Omron CX-Programmer project 新工程 (CX-Programmer 9.50)

# PLC 新PLC1: CP1E N14

## Global symbols (name address type ; comment)
0.00 BOOL  ; 编码器输入
0.04 BOOL  ; 工位1剔除输入
0.05 BOOL  ; 工位2剔除输入
0.06 BOOL  ; 工位3剔除输入
0.07 BOOL  ; 喷码剔除输入
100.00 BOOL  ; 剔除输出
100.01 BOOL  ; 剔除
D0 CHANNEL  ; 1#计数器当前值
D10 CHANNEL  ; 一
D12 CHANNEL  ; 一
D14 CHANNEL  ; 一
D16 CHANNEL  ; 一
D18 CHANNEL  ; 一
D2 CHANNEL  ; 一
D20 CHANNEL  ; 一
D200 CHANNEL  ; 2#计数器当前值
D2000 CHANNEL  ; 相机1脉冲数
D2002 CHANNEL  ; 相机2脉冲数
D2004 CHANNEL  ; 相机3脉冲数
D2006 CHANNEL  ; 相机4脉冲数
D2008 CHANNEL  ; 吹气时间
D202 CHANNEL  ; 二
D204 CHANNEL  ; 二
D206 CHANNEL  ; 二
D208 CHANNEL  ; 二
D210 CHANNEL  ; 二
D212 CHANNEL  ; 二
D214 CHANNEL  ; 二
D216 CHANNEL  ; 二
D218 CHANNEL  ; 二
D22 CHANNEL  ; 一
D220 CHANNEL  ; 二
D222 CHANNEL  ; 二
D224 CHANNEL  ; 二
D226 CHANNEL  ; 二
D228 CHANNEL  ; 二
D230 CHANNEL  ; 二
D232 CHANNEL  ; 二
D234 CHANNEL  ; 二
D236 CHANNEL  ; 二
D238 CHANNEL  ; 二
D24 CHANNEL  ; 一
D240 CHANNEL  ; 二
D242 CHANNEL  ; 二
D244 CHANNEL  ; 二
D246 CHANNEL  ; 二
D248 CHANNEL  ; 二
D250 CHANNEL  ; 二
D252 CHANNEL  ; 二
D254 CHANNEL  ; 二
D256 CHANNEL  ; 二
D258 CHANNEL  ; 二
D26 CHANNEL  ; 一
D260 CHANNEL  ; 二
D28 CHANNEL  ; 一
D30 CHANNEL  ; 一
D32 CHANNEL  ; 一
D34 CHANNEL  ; 一
D36 CHANNEL  ; 一
D38 CHANNEL  ; 一
D4 CHANNEL  ; 一
D40 CHANNEL  ; 一
D402 CHANNEL  ; 三
D404 CHANNEL  ; 三
D406 CHANNEL  ; 三
D408 CHANNEL  ; 三
D410 CHANNEL  ; 三
D412 CHANNEL  ; 三
D414 CHANNEL  ; 三
D416 CHANNEL  ; 三
D418 CHANNEL  ; 三
D42 CHANNEL  ; 一
D420 CHANNEL  ; 三
D422 CHANNEL  ; 三
D424 CHANNEL  ; 三
D426 CHANNEL  ; 三
D428 CHANNEL  ; 三
D430 CHANNEL  ; 三
D432 CHANNEL  ; 三
D434 CHANNEL  ; 三
D436 CHANNEL  ; 三
D438 CHANNEL  ; 三
D44 CHANNEL  ; 一
D440 CHANNEL  ; 三
D442 CHANNEL  ; 三
D444 CHANNEL  ; 三
D446 CHANNEL  ; 三
D448 CHANNEL  ; 三
D450 CHANNEL  ; 三
D452 CHANNEL  ; 三
D454 CHANNEL  ; 三
D456 CHANNEL  ; 三
D458 CHANNEL  ; 三
D46 CHANNEL  ; 一
D460 CHANNEL  ; 三
D48 CHANNEL  ; 一
D50 CHANNEL  ; 一
D52 CHANNEL  ; 一
D54 CHANNEL  ; 一
D56 CHANNEL  ; 一
D58 CHANNEL  ; 一
D6 CHANNEL  ; 一
D60 CHANNEL  ; 一
D6000 CHANNEL  ; 喷码延时时间
D602 CHANNEL  ; 四
D604 CHANNEL  ; 四
D606 CHANNEL  ; 四
D608 CHANNEL  ; 四
D610 CHANNEL  ; 四
D612 CHANNEL  ; 四
D614 CHANNEL  ; 四
D616 CHANNEL  ; 四
D618 CHANNEL  ; 四
D620 CHANNEL  ; 四
D622 CHANNEL  ; 四
D624 CHANNEL  ; 四
D626 CHANNEL  ; 四
D628 CHANNEL  ; 四
D630 CHANNEL  ; 四
D632 CHANNEL  ; 四
D634 CHANNEL  ; 四
D636 CHANNEL  ; 四
D638 CHANNEL  ; 四
D640 CHANNEL  ; 四
D642 CHANNEL  ; 四
D644 CHANNEL  ; 四
D646 CHANNEL  ; 四
D648 CHANNEL  ; 四
D650 CHANNEL  ; 四
D652 CHANNEL  ; 四
D654 CHANNEL  ; 四
D656 CHANNEL  ; 四
D658 CHANNEL  ; 四
D660 CHANNEL  ; 四
D8 CHANNEL  ; 一
W0.00 BOOL  ; 一
W0.01 BOOL  ; 一
W0.02 BOOL  ; 一
W0.03 BOOL  ; 一
W0.04 BOOL  ; 一
W0.05 BOOL  ; 一
W0.06 BOOL  ; 一
W0.07 BOOL  ; 一
W0.08 BOOL  ; 一
W0.09 BOOL  ; 一
W0.10 BOOL  ; 一
W0.11 BOOL  ; 一
W0.12 BOOL  ; 一
W0.13 BOOL  ; 一
W0.14 BOOL  ; 一
W0.15 BOOL  ; 一
W10.00 BOOL  ; 二
W10.01 BOOL  ; 二
W10.02 BOOL  ; 二
W10.03 BOOL  ; 二
W10.04 BOOL  ; 二
W10.05 BOOL  ; 二
W10.06 BOOL  ; 二
W10.07 BOOL  ; 二
W10.08 BOOL  ; 二
W10.09 BOOL  ; 二
W10.10 BOOL  ; 二
W10.11 BOOL  ; 二
W10.12 BOOL  ; 二
W10.13 BOOL  ; 二
W10.14 BOOL  ; 二
W10.15 BOOL  ; 二
W11.00 BOOL  ; 二
W11.01 BOOL  ; 二
W11.02 BOOL  ; 二
W11.03 BOOL  ; 二
W11.04 BOOL  ; 二
W11.05 BOOL  ; 二
W11.06 BOOL  ; 二
W11.07 BOOL  ; 二
W11.08 BOOL  ; 二
W11.09 BOOL  ; 二
W11.10 BOOL  ; 二
W11.11 BOOL  ; 二
W11.12 BOOL  ; 二
W11.13 BOOL  ; 二
W11.14 BOOL  ; 二
W11.15 BOOL  ; 二
W1.00 BOOL  ; 一
W1.01 BOOL  ; 一
W1.02 BOOL  ; 一
W1.03 BOOL  ; 一
W1.04 BOOL  ; 一
W1.05 BOOL  ; 一
W1.06 BOOL  ; 一
W1.07 BOOL  ; 一
W1.08 BOOL  ; 一
W1.09 BOOL  ; 一
W1.10 BOOL  ; 一
W1.11 BOOL  ; 一
W1.12 BOOL  ; 一
W1.13 BOOL  ; 一
W1.14 BOOL  ; 一
W1.15 BOOL  ; 一
W20.00 BOOL  ; 三
W20.01 BOOL  ; 三
W20.02 BOOL  ; 三
W20.03 BOOL  ; 三
W20.04 BOOL  ; 三
W20.05 BOOL  ; 三
W20.06 BOOL  ; 三
W20.07 BOOL  ; 三
W20.08 BOOL  ; 三
W20.09 BOOL  ; 三
W20.10 BOOL  ; 三
W20.11 BOOL  ; 三
W20.12 BOOL  ; 三
W20.13 BOOL  ; 三
W20.14 BOOL  ; 三
W20.15 BOOL  ; 三
W21.00 BOOL  ; 三
W21.01 BOOL  ; 三
W21.02 BOOL  ; 三
W21.03 BOOL  ; 三
W21.04 BOOL  ; 三
W21.05 BOOL  ; 三
W21.06 BOOL  ; 三
W21.07 BOOL  ; 三
W21.08 BOOL  ; 三
W21.09 BOOL  ; 三
W21.10 BOOL  ; 三
W21.11 BOOL  ; 三
W21.12 BOOL  ; 三
W21.13 BOOL  ; 三
W21.14 BOOL  ; 三
W21.15 BOOL  ; 三
W30.00 BOOL  ; 四五
W30.01 BOOL  ; 四五
W30.02 BOOL  ; 四五
W30.03 BOOL  ; 四五
W30.04 BOOL  ; 四五
W30.05 BOOL  ; 四五
W30.06 BOOL  ; 四五
W30.07 BOOL  ; 四五
W30.08 BOOL  ; 四五
W30.09 BOOL  ; 四五
W30.10 BOOL  ; 四五
W30.11 BOOL  ; 四五
W30.12 BOOL  ; 四五
W30.13 BOOL  ; 四五
W30.14 BOOL  ; 四五
W30.15 BOOL  ; 四五
W31.00 BOOL  ; 四五
W31.01 BOOL  ; 四五
W31.02 BOOL  ; 四五
W31.03 BOOL  ; 四五
W31.04 BOOL  ; 四五
W31.05 BOOL  ; 四五
W31.06 BOOL  ; 四五
W31.07 BOOL  ; 四五
W31.08 BOOL  ; 四五
W31.09 BOOL  ; 四五
W31.10 BOOL  ; 四五
W31.11 BOOL  ; 四五
W31.12 BOOL  ; 四五
W31.13 BOOL  ; 四五
W31.14 BOOL  ; 四五
W31.15 BOOL  ; 四五

## Program 新程序1 (cyclic task 0)

### Section 脉冲设置

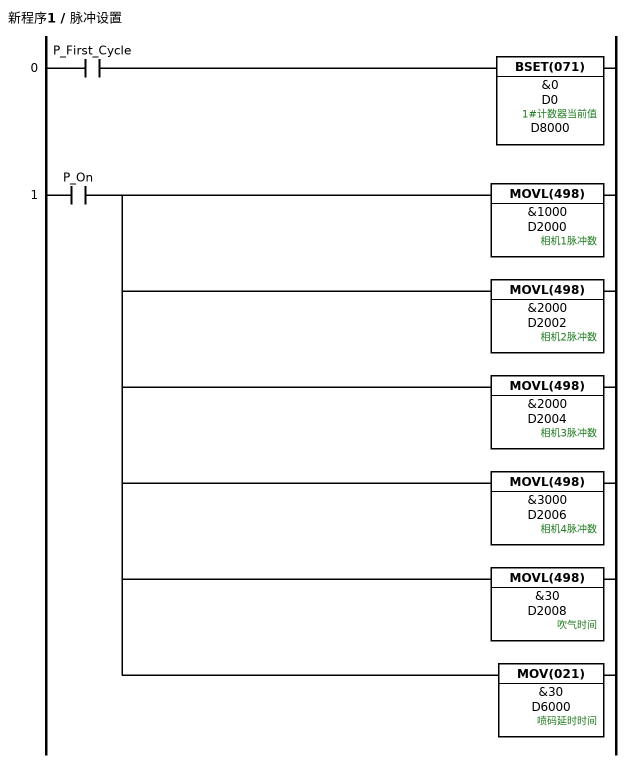
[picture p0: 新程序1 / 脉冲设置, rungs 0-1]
; rung 0
LD P_First_Cycle
BSET(071) &0 D0 D8000  ; 1#计数器当前值
; rung 1
LD P_On
MOVL(498) &1000 D2000  ; 相机1脉冲数
MOVL(498) &2000 D2002  ; 相机2脉冲数
MOVL(498) &2000 D2004  ; 相机3脉冲数
MOVL(498) &3000 D2006  ; 相机4脉冲数
MOVL(498) &30 D2008  ; 吹气时间
MOV(021) &30 D6000  ; 喷码延时时间

### Section 计数器设置

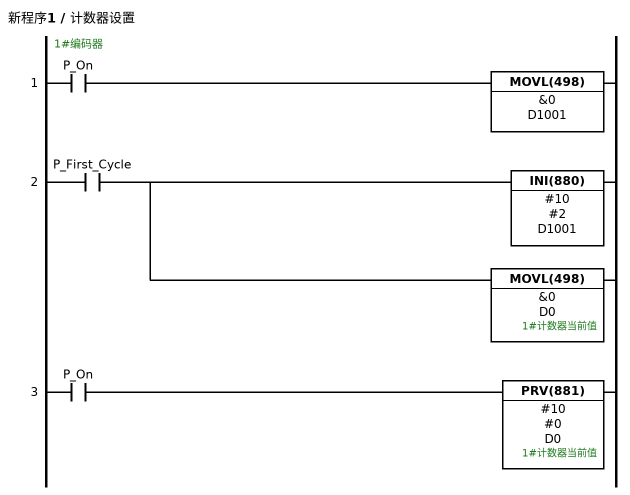
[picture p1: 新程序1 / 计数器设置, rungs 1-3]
; rung 1: 1#编码器
LD P_On
MOVL(498) &0 D1001
; rung 2
LD P_First_Cycle
INI(880) #10 #2 D1001
MOVL(498) &0 D0  ; 1#计数器当前值
; rung 3
LD P_On
PRV(881) #10 #0 D0  ; 1#计数器当前值

### Section 相机1剔除

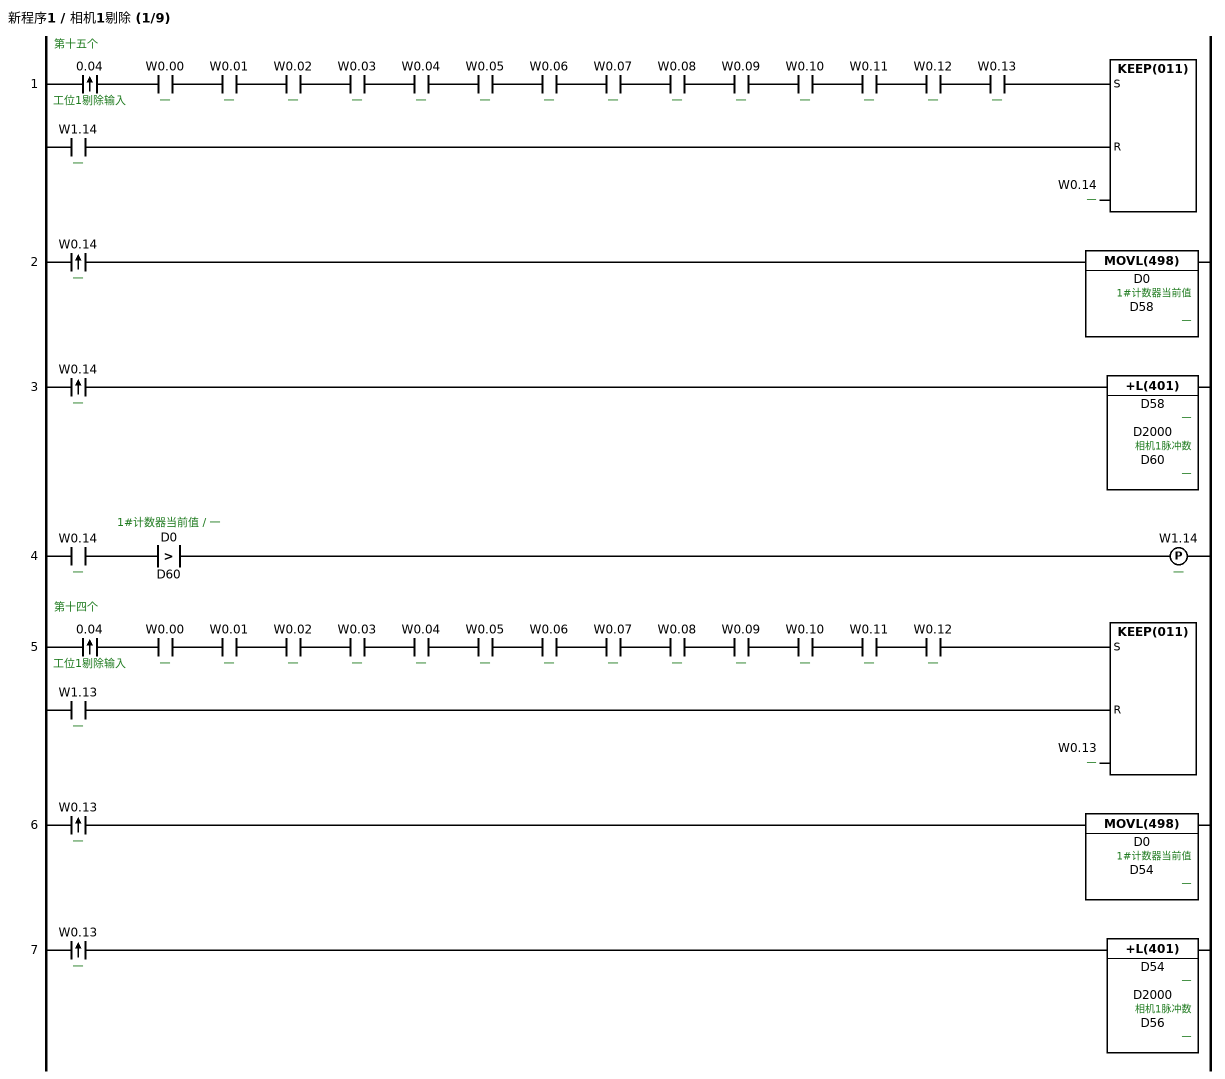
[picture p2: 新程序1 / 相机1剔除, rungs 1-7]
; rung 1: 第十五个
@LD 0.04  ; 工位1剔除输入
AND W0.00  ; 一
AND W0.01  ; 一
AND W0.02  ; 一
AND W0.03  ; 一
AND W0.04  ; 一
AND W0.05  ; 一
AND W0.06  ; 一
AND W0.07  ; 一
AND W0.08  ; 一
AND W0.09  ; 一
AND W0.10  ; 一
AND W0.11  ; 一
AND W0.12  ; 一
AND W0.13  ; 一
LD W1.14  ; 一
KEEP(011) W0.14  ; 一
; rung 2
@LD W0.14  ; 一
MOVL(498) D0 D58  ; 1#计数器当前值, 一
; rung 3
@LD W0.14  ; 一
+L(401) D58 D2000 D60  ; 一, 相机1脉冲数
; rung 4
LD W0.14  ; 一
AND>L(321) D0 D60  ; 1#计数器当前值, 一
DIFU(013) W1.14  ; 一
; rung 5: 第十四个
@LD 0.04  ; 工位1剔除输入
AND W0.00  ; 一
AND W0.01  ; 一
AND W0.02  ; 一
AND W0.03  ; 一
AND W0.04  ; 一
AND W0.05  ; 一
AND W0.06  ; 一
AND W0.07  ; 一
AND W0.08  ; 一
AND W0.09  ; 一
AND W0.10  ; 一
AND W0.11  ; 一
AND W0.12  ; 一
LD W1.13  ; 一
KEEP(011) W0.13  ; 一
; rung 6
@LD W0.13  ; 一
MOVL(498) D0 D54  ; 1#计数器当前值, 一
; rung 7
@LD W0.13  ; 一
+L(401) D54 D2000 D56  ; 一, 相机1脉冲数

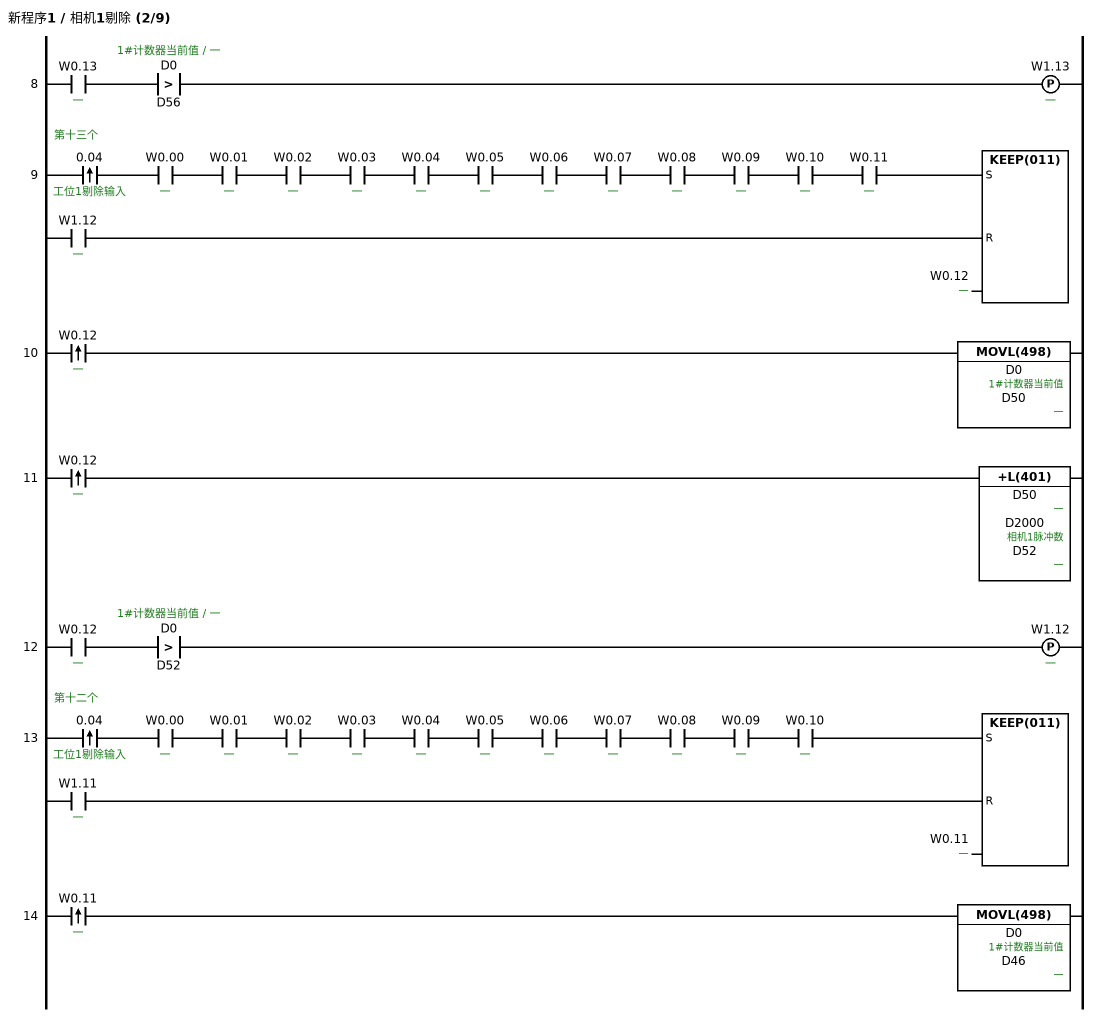
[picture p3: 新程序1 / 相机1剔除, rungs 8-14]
; rung 8
LD W0.13  ; 一
AND>L(321) D0 D56  ; 1#计数器当前值, 一
DIFU(013) W1.13  ; 一
; rung 9: 第十三个
@LD 0.04  ; 工位1剔除输入
AND W0.00  ; 一
AND W0.01  ; 一
AND W0.02  ; 一
AND W0.03  ; 一
AND W0.04  ; 一
AND W0.05  ; 一
AND W0.06  ; 一
AND W0.07  ; 一
AND W0.08  ; 一
AND W0.09  ; 一
AND W0.10  ; 一
AND W0.11  ; 一
LD W1.12  ; 一
KEEP(011) W0.12  ; 一
; rung 10
@LD W0.12  ; 一
MOVL(498) D0 D50  ; 1#计数器当前值, 一
; rung 11
@LD W0.12  ; 一
+L(401) D50 D2000 D52  ; 一, 相机1脉冲数
; rung 12
LD W0.12  ; 一
AND>L(321) D0 D52  ; 1#计数器当前值, 一
DIFU(013) W1.12  ; 一
; rung 13: 第十二个
@LD 0.04  ; 工位1剔除输入
AND W0.00  ; 一
AND W0.01  ; 一
AND W0.02  ; 一
AND W0.03  ; 一
AND W0.04  ; 一
AND W0.05  ; 一
AND W0.06  ; 一
AND W0.07  ; 一
AND W0.08  ; 一
AND W0.09  ; 一
AND W0.10  ; 一
LD W1.11  ; 一
KEEP(011) W0.11  ; 一
; rung 14
@LD W0.11  ; 一
MOVL(498) D0 D46  ; 1#计数器当前值, 一

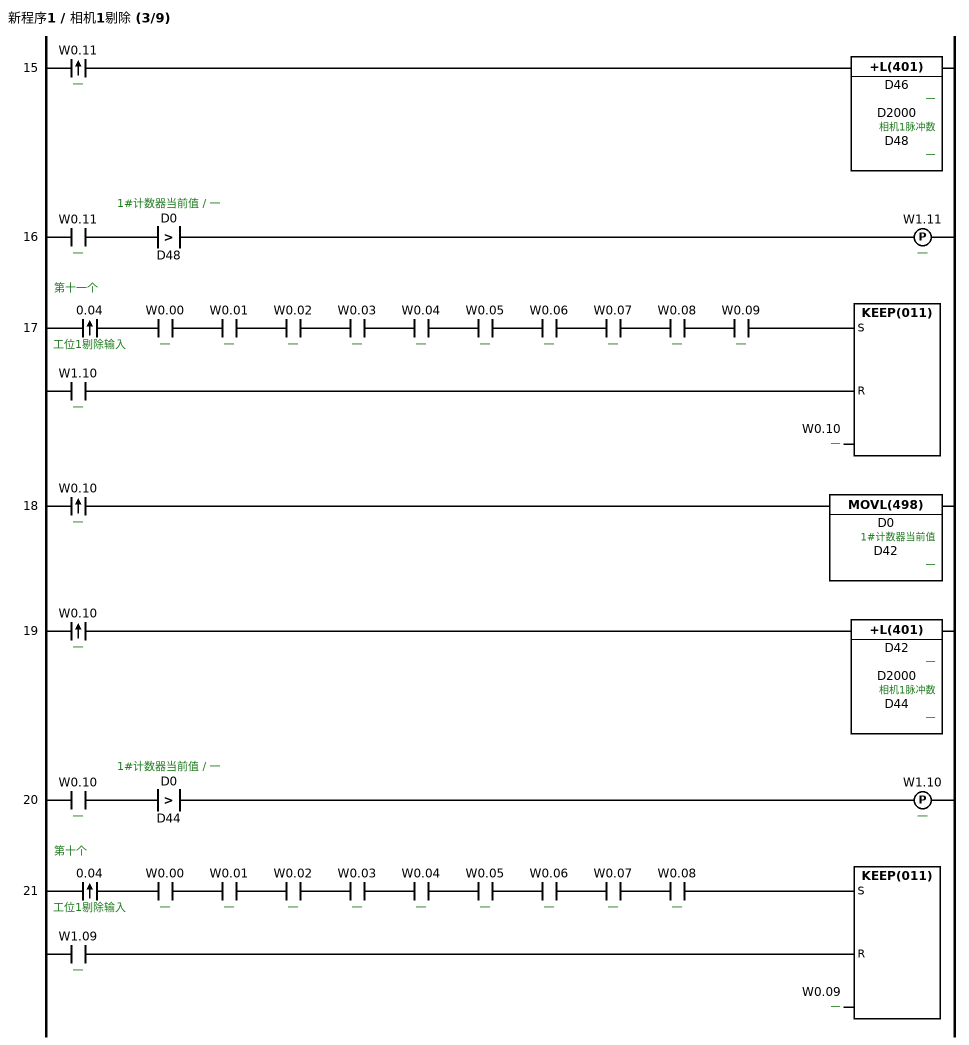
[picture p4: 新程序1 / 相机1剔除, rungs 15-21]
; rung 15
@LD W0.11  ; 一
+L(401) D46 D2000 D48  ; 一, 相机1脉冲数
; rung 16
LD W0.11  ; 一
AND>L(321) D0 D48  ; 1#计数器当前值, 一
DIFU(013) W1.11  ; 一
; rung 17: 第十一个
@LD 0.04  ; 工位1剔除输入
AND W0.00  ; 一
AND W0.01  ; 一
AND W0.02  ; 一
AND W0.03  ; 一
AND W0.04  ; 一
AND W0.05  ; 一
AND W0.06  ; 一
AND W0.07  ; 一
AND W0.08  ; 一
AND W0.09  ; 一
LD W1.10  ; 一
KEEP(011) W0.10  ; 一
; rung 18
@LD W0.10  ; 一
MOVL(498) D0 D42  ; 1#计数器当前值, 一
; rung 19
@LD W0.10  ; 一
+L(401) D42 D2000 D44  ; 一, 相机1脉冲数
; rung 20
LD W0.10  ; 一
AND>L(321) D0 D44  ; 1#计数器当前值, 一
DIFU(013) W1.10  ; 一
; rung 21: 第十个
@LD 0.04  ; 工位1剔除输入
AND W0.00  ; 一
AND W0.01  ; 一
AND W0.02  ; 一
AND W0.03  ; 一
AND W0.04  ; 一
AND W0.05  ; 一
AND W0.06  ; 一
AND W0.07  ; 一
AND W0.08  ; 一
LD W1.09  ; 一
KEEP(011) W0.09  ; 一

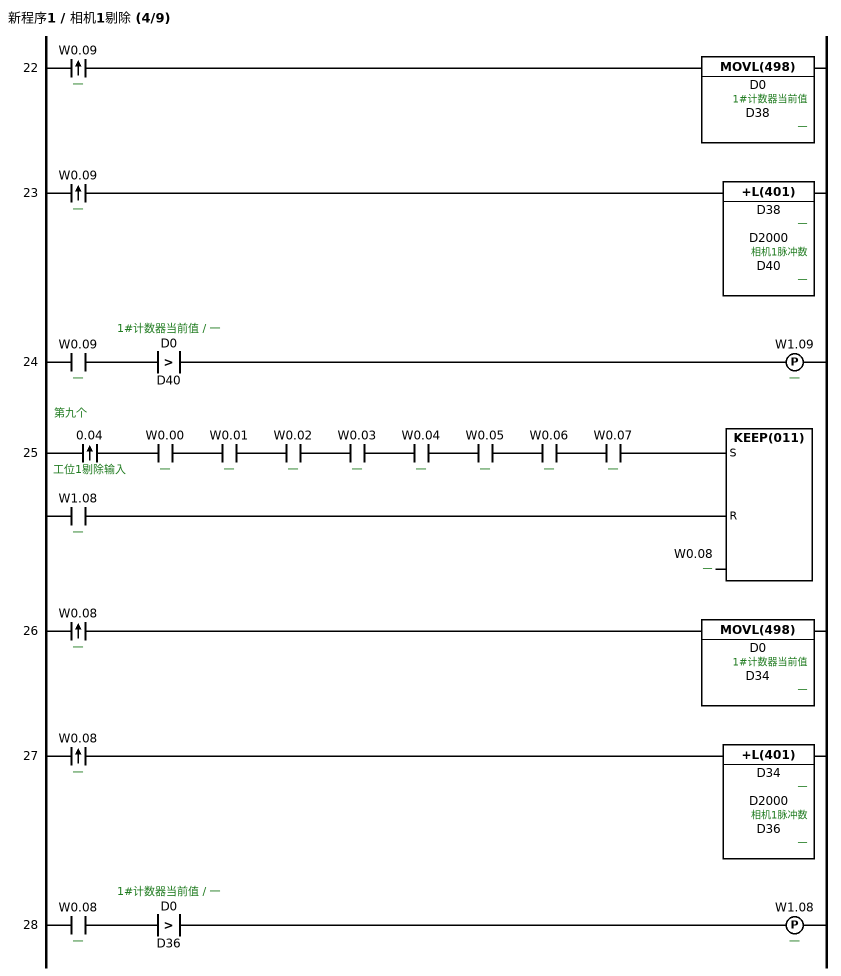
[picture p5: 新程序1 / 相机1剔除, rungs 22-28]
; rung 22
@LD W0.09  ; 一
MOVL(498) D0 D38  ; 1#计数器当前值, 一
; rung 23
@LD W0.09  ; 一
+L(401) D38 D2000 D40  ; 一, 相机1脉冲数
; rung 24
LD W0.09  ; 一
AND>L(321) D0 D40  ; 1#计数器当前值, 一
DIFU(013) W1.09  ; 一
; rung 25: 第九个
@LD 0.04  ; 工位1剔除输入
AND W0.00  ; 一
AND W0.01  ; 一
AND W0.02  ; 一
AND W0.03  ; 一
AND W0.04  ; 一
AND W0.05  ; 一
AND W0.06  ; 一
AND W0.07  ; 一
LD W1.08  ; 一
KEEP(011) W0.08  ; 一
; rung 26
@LD W0.08  ; 一
MOVL(498) D0 D34  ; 1#计数器当前值, 一
; rung 27
@LD W0.08  ; 一
+L(401) D34 D2000 D36  ; 一, 相机1脉冲数
; rung 28
LD W0.08  ; 一
AND>L(321) D0 D36  ; 1#计数器当前值, 一
DIFU(013) W1.08  ; 一

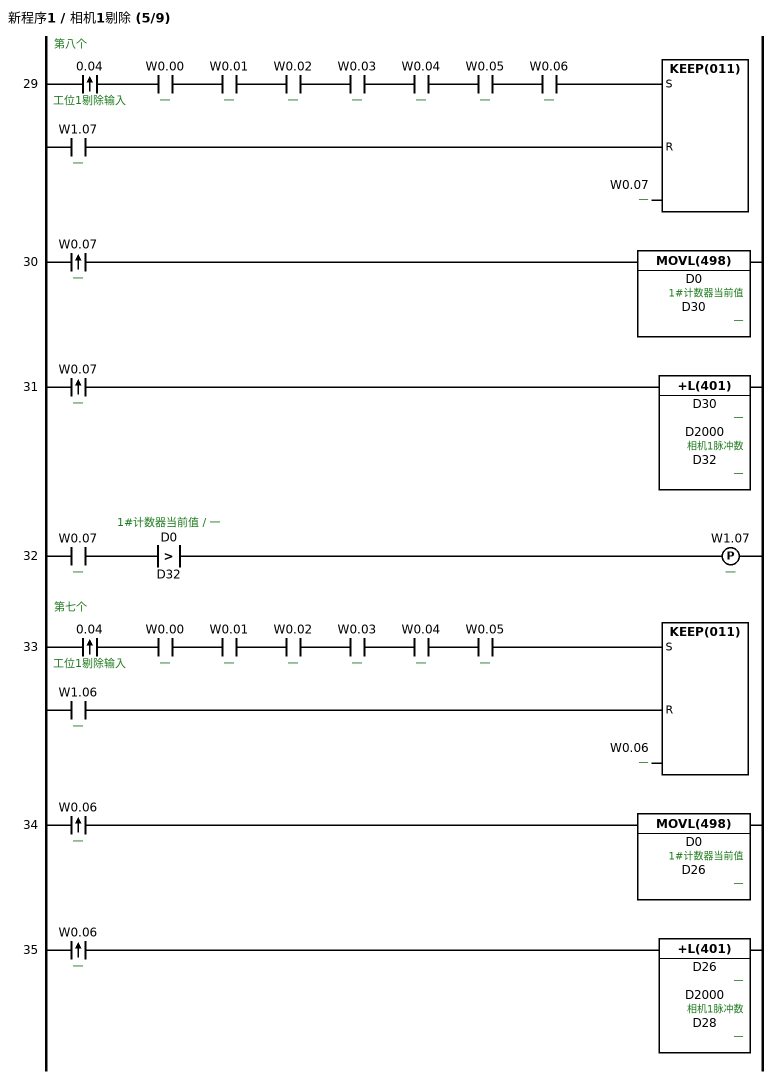
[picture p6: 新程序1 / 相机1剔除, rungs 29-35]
; rung 29: 第八个
@LD 0.04  ; 工位1剔除输入
AND W0.00  ; 一
AND W0.01  ; 一
AND W0.02  ; 一
AND W0.03  ; 一
AND W0.04  ; 一
AND W0.05  ; 一
AND W0.06  ; 一
LD W1.07  ; 一
KEEP(011) W0.07  ; 一
; rung 30
@LD W0.07  ; 一
MOVL(498) D0 D30  ; 1#计数器当前值, 一
; rung 31
@LD W0.07  ; 一
+L(401) D30 D2000 D32  ; 一, 相机1脉冲数
; rung 32
LD W0.07  ; 一
AND>L(321) D0 D32  ; 1#计数器当前值, 一
DIFU(013) W1.07  ; 一
; rung 33: 第七个
@LD 0.04  ; 工位1剔除输入
AND W0.00  ; 一
AND W0.01  ; 一
AND W0.02  ; 一
AND W0.03  ; 一
AND W0.04  ; 一
AND W0.05  ; 一
LD W1.06  ; 一
KEEP(011) W0.06  ; 一
; rung 34
@LD W0.06  ; 一
MOVL(498) D0 D26  ; 1#计数器当前值, 一
; rung 35
@LD W0.06  ; 一
+L(401) D26 D2000 D28  ; 一, 相机1脉冲数

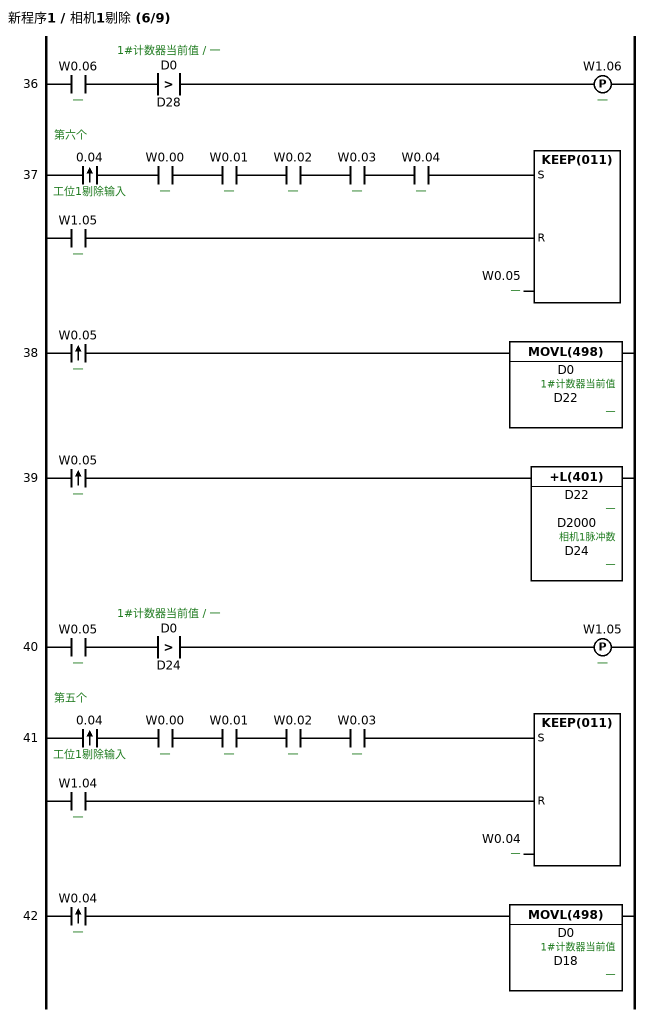
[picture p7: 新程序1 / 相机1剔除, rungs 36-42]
; rung 36
LD W0.06  ; 一
AND>L(321) D0 D28  ; 1#计数器当前值, 一
DIFU(013) W1.06  ; 一
; rung 37: 第六个
@LD 0.04  ; 工位1剔除输入
AND W0.00  ; 一
AND W0.01  ; 一
AND W0.02  ; 一
AND W0.03  ; 一
AND W0.04  ; 一
LD W1.05  ; 一
KEEP(011) W0.05  ; 一
; rung 38
@LD W0.05  ; 一
MOVL(498) D0 D22  ; 1#计数器当前值, 一
; rung 39
@LD W0.05  ; 一
+L(401) D22 D2000 D24  ; 一, 相机1脉冲数
; rung 40
LD W0.05  ; 一
AND>L(321) D0 D24  ; 1#计数器当前值, 一
DIFU(013) W1.05  ; 一
; rung 41: 第五个
@LD 0.04  ; 工位1剔除输入
AND W0.00  ; 一
AND W0.01  ; 一
AND W0.02  ; 一
AND W0.03  ; 一
LD W1.04  ; 一
KEEP(011) W0.04  ; 一
; rung 42
@LD W0.04  ; 一
MOVL(498) D0 D18  ; 1#计数器当前值, 一

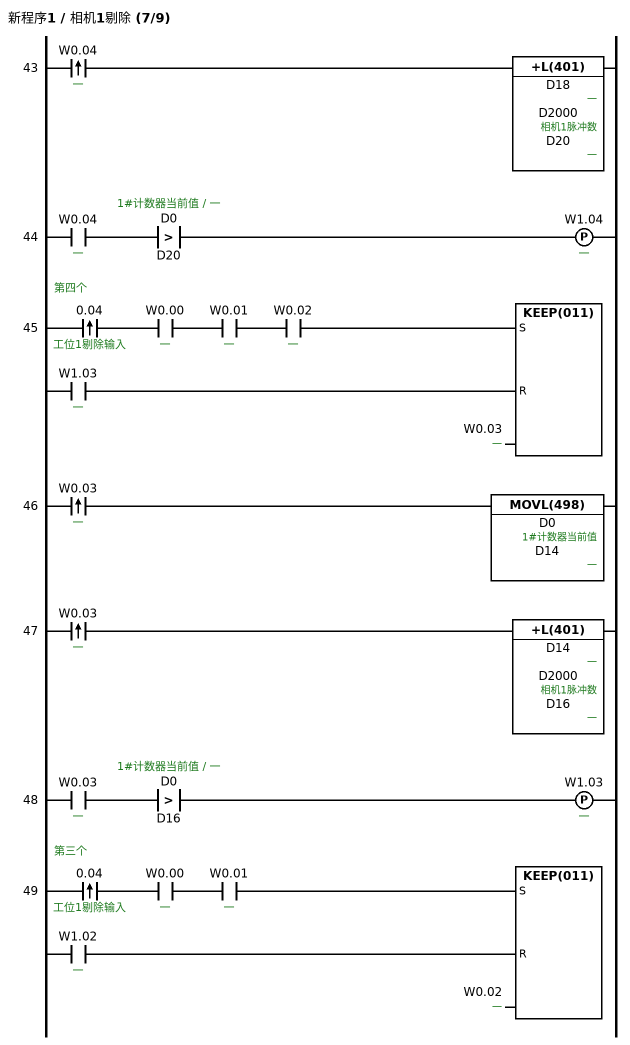
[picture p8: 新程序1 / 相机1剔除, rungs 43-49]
; rung 43
@LD W0.04  ; 一
+L(401) D18 D2000 D20  ; 一, 相机1脉冲数
; rung 44
LD W0.04  ; 一
AND>L(321) D0 D20  ; 1#计数器当前值, 一
DIFU(013) W1.04  ; 一
; rung 45: 第四个
@LD 0.04  ; 工位1剔除输入
AND W0.00  ; 一
AND W0.01  ; 一
AND W0.02  ; 一
LD W1.03  ; 一
KEEP(011) W0.03  ; 一
; rung 46
@LD W0.03  ; 一
MOVL(498) D0 D14  ; 1#计数器当前值, 一
; rung 47
@LD W0.03  ; 一
+L(401) D14 D2000 D16  ; 一, 相机1脉冲数
; rung 48
LD W0.03  ; 一
AND>L(321) D0 D16  ; 1#计数器当前值, 一
DIFU(013) W1.03  ; 一
; rung 49: 第三个
@LD 0.04  ; 工位1剔除输入
AND W0.00  ; 一
AND W0.01  ; 一
LD W1.02  ; 一
KEEP(011) W0.02  ; 一

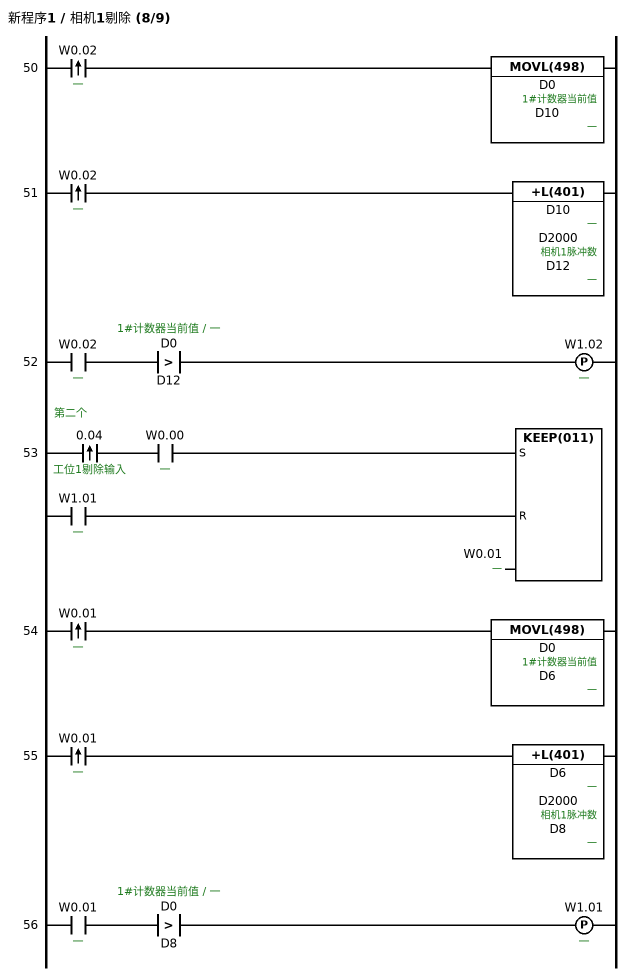
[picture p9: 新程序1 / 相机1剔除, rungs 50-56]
; rung 50
@LD W0.02  ; 一
MOVL(498) D0 D10  ; 1#计数器当前值, 一
; rung 51
@LD W0.02  ; 一
+L(401) D10 D2000 D12  ; 一, 相机1脉冲数
; rung 52
LD W0.02  ; 一
AND>L(321) D0 D12  ; 1#计数器当前值, 一
DIFU(013) W1.02  ; 一
; rung 53: 第二个
@LD 0.04  ; 工位1剔除输入
AND W0.00  ; 一
LD W1.01  ; 一
KEEP(011) W0.01  ; 一
; rung 54
@LD W0.01  ; 一
MOVL(498) D0 D6  ; 1#计数器当前值, 一
; rung 55
@LD W0.01  ; 一
+L(401) D6 D2000 D8  ; 一, 相机1脉冲数
; rung 56
LD W0.01  ; 一
AND>L(321) D0 D8  ; 1#计数器当前值, 一
DIFU(013) W1.01  ; 一

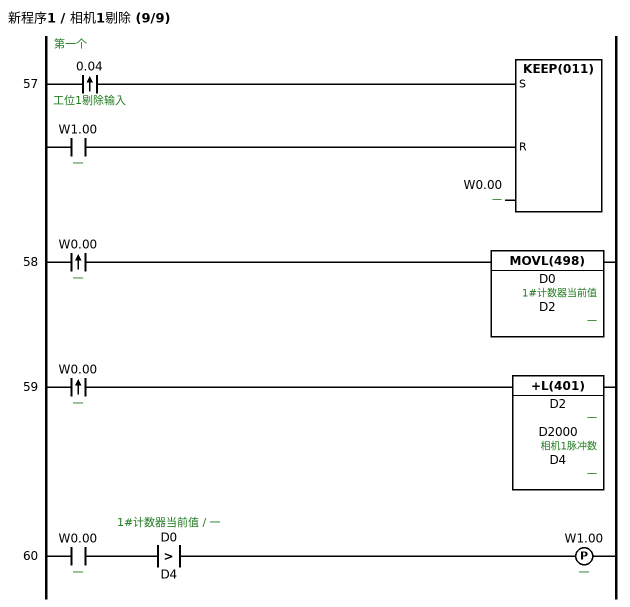
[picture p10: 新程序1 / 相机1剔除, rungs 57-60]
; rung 57: 第一个
@LD 0.04  ; 工位1剔除输入
LD W1.00  ; 一
KEEP(011) W0.00  ; 一
; rung 58
@LD W0.00  ; 一
MOVL(498) D0 D2  ; 1#计数器当前值, 一
; rung 59
@LD W0.00  ; 一
+L(401) D2 D2000 D4  ; 一, 相机1脉冲数
; rung 60
LD W0.00  ; 一
AND>L(321) D0 D4  ; 1#计数器当前值, 一
DIFU(013) W1.00  ; 一

### Section 相机2剔除

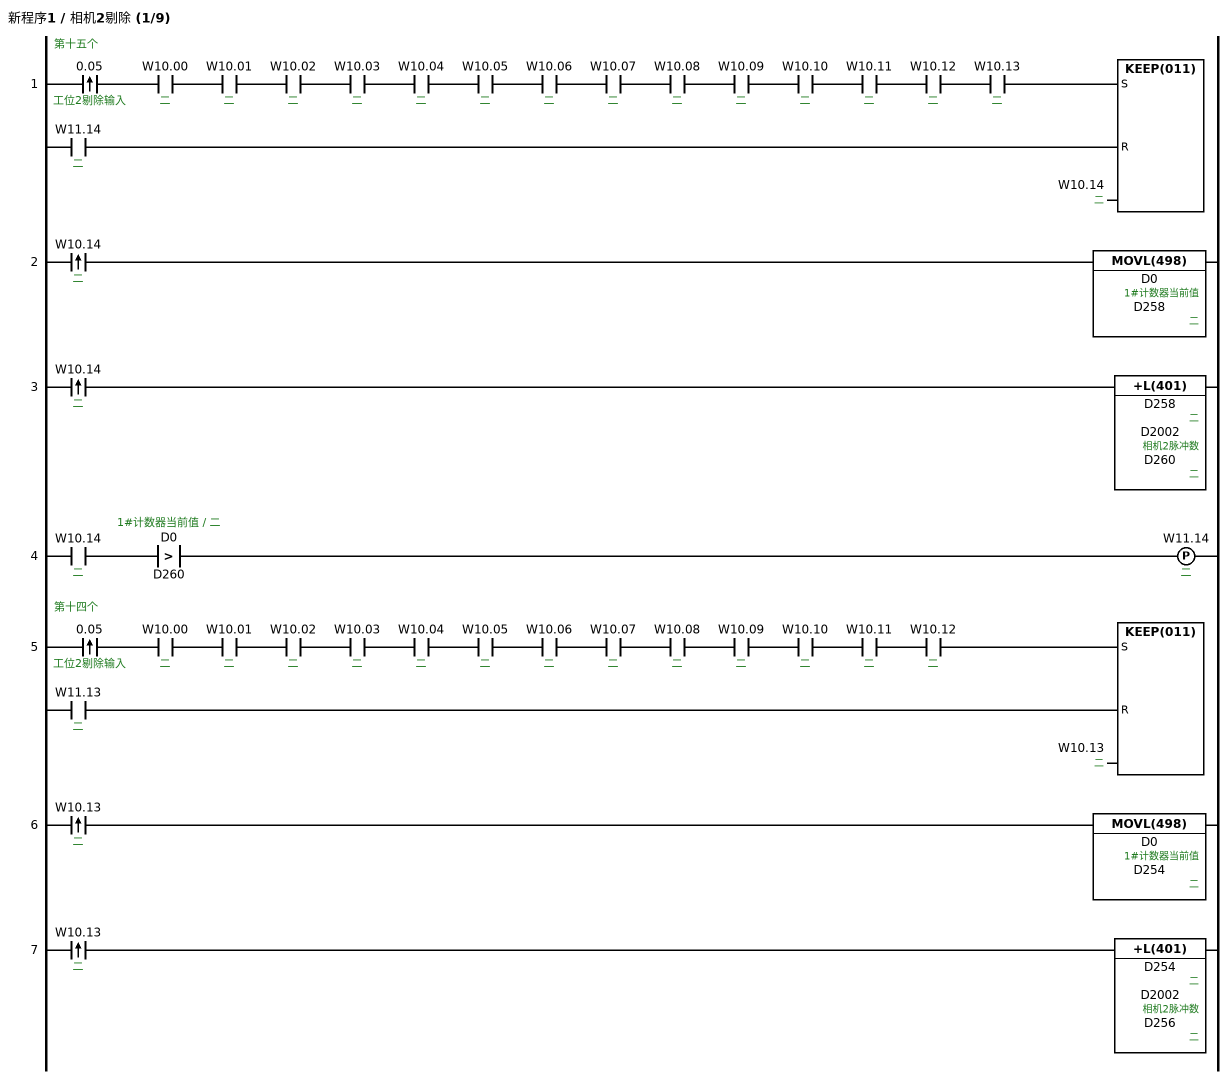
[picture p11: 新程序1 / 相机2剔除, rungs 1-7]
; rung 1: 第十五个
@LD 0.05  ; 工位2剔除输入
AND W10.00  ; 二
AND W10.01  ; 二
AND W10.02  ; 二
AND W10.03  ; 二
AND W10.04  ; 二
AND W10.05  ; 二
AND W10.06  ; 二
AND W10.07  ; 二
AND W10.08  ; 二
AND W10.09  ; 二
AND W10.10  ; 二
AND W10.11  ; 二
AND W10.12  ; 二
AND W10.13  ; 二
LD W11.14  ; 二
KEEP(011) W10.14  ; 二
; rung 2
@LD W10.14  ; 二
MOVL(498) D0 D258  ; 1#计数器当前值, 二
; rung 3
@LD W10.14  ; 二
+L(401) D258 D2002 D260  ; 二, 相机2脉冲数
; rung 4
LD W10.14  ; 二
AND>L(321) D0 D260  ; 1#计数器当前值, 二
DIFU(013) W11.14  ; 二
; rung 5: 第十四个
@LD 0.05  ; 工位2剔除输入
AND W10.00  ; 二
AND W10.01  ; 二
AND W10.02  ; 二
AND W10.03  ; 二
AND W10.04  ; 二
AND W10.05  ; 二
AND W10.06  ; 二
AND W10.07  ; 二
AND W10.08  ; 二
AND W10.09  ; 二
AND W10.10  ; 二
AND W10.11  ; 二
AND W10.12  ; 二
LD W11.13  ; 二
KEEP(011) W10.13  ; 二
; rung 6
@LD W10.13  ; 二
MOVL(498) D0 D254  ; 1#计数器当前值, 二
; rung 7
@LD W10.13  ; 二
+L(401) D254 D2002 D256  ; 二, 相机2脉冲数

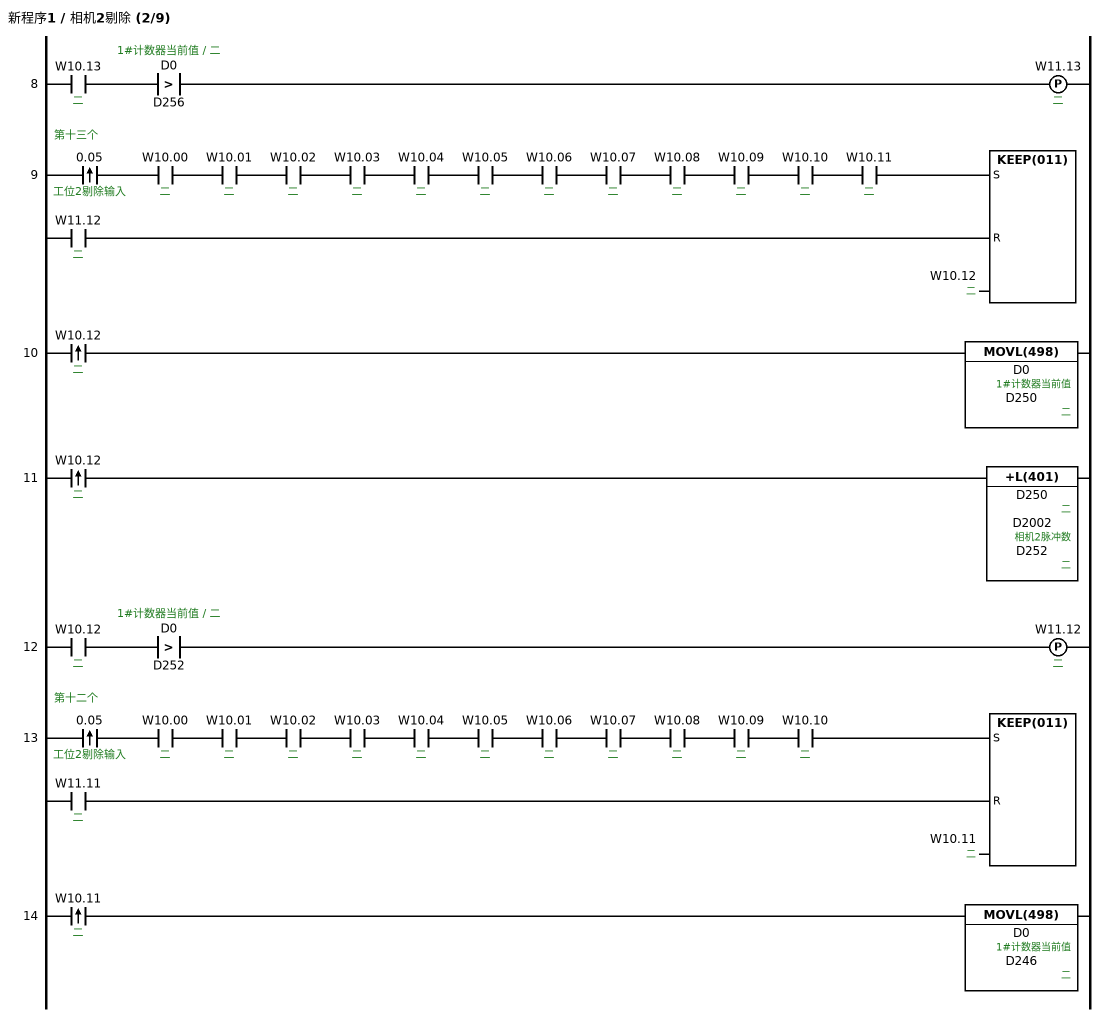
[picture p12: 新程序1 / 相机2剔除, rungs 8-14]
; rung 8
LD W10.13  ; 二
AND>L(321) D0 D256  ; 1#计数器当前值, 二
DIFU(013) W11.13  ; 二
; rung 9: 第十三个
@LD 0.05  ; 工位2剔除输入
AND W10.00  ; 二
AND W10.01  ; 二
AND W10.02  ; 二
AND W10.03  ; 二
AND W10.04  ; 二
AND W10.05  ; 二
AND W10.06  ; 二
AND W10.07  ; 二
AND W10.08  ; 二
AND W10.09  ; 二
AND W10.10  ; 二
AND W10.11  ; 二
LD W11.12  ; 二
KEEP(011) W10.12  ; 二
; rung 10
@LD W10.12  ; 二
MOVL(498) D0 D250  ; 1#计数器当前值, 二
; rung 11
@LD W10.12  ; 二
+L(401) D250 D2002 D252  ; 二, 相机2脉冲数
; rung 12
LD W10.12  ; 二
AND>L(321) D0 D252  ; 1#计数器当前值, 二
DIFU(013) W11.12  ; 二
; rung 13: 第十二个
@LD 0.05  ; 工位2剔除输入
AND W10.00  ; 二
AND W10.01  ; 二
AND W10.02  ; 二
AND W10.03  ; 二
AND W10.04  ; 二
AND W10.05  ; 二
AND W10.06  ; 二
AND W10.07  ; 二
AND W10.08  ; 二
AND W10.09  ; 二
AND W10.10  ; 二
LD W11.11  ; 二
KEEP(011) W10.11  ; 二
; rung 14
@LD W10.11  ; 二
MOVL(498) D0 D246  ; 1#计数器当前值, 二

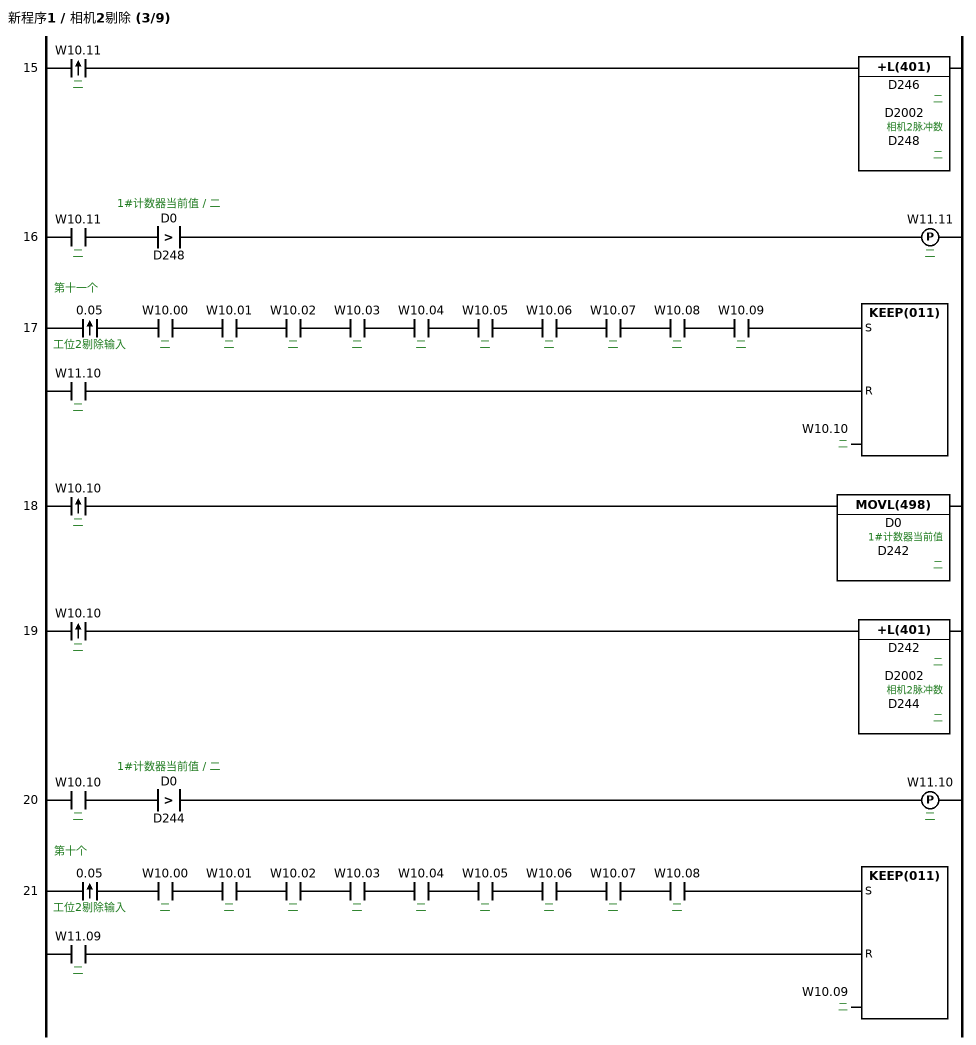
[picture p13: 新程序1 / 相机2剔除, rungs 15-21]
; rung 15
@LD W10.11  ; 二
+L(401) D246 D2002 D248  ; 二, 相机2脉冲数
; rung 16
LD W10.11  ; 二
AND>L(321) D0 D248  ; 1#计数器当前值, 二
DIFU(013) W11.11  ; 二
; rung 17: 第十一个
@LD 0.05  ; 工位2剔除输入
AND W10.00  ; 二
AND W10.01  ; 二
AND W10.02  ; 二
AND W10.03  ; 二
AND W10.04  ; 二
AND W10.05  ; 二
AND W10.06  ; 二
AND W10.07  ; 二
AND W10.08  ; 二
AND W10.09  ; 二
LD W11.10  ; 二
KEEP(011) W10.10  ; 二
; rung 18
@LD W10.10  ; 二
MOVL(498) D0 D242  ; 1#计数器当前值, 二
; rung 19
@LD W10.10  ; 二
+L(401) D242 D2002 D244  ; 二, 相机2脉冲数
; rung 20
LD W10.10  ; 二
AND>L(321) D0 D244  ; 1#计数器当前值, 二
DIFU(013) W11.10  ; 二
; rung 21: 第十个
@LD 0.05  ; 工位2剔除输入
AND W10.00  ; 二
AND W10.01  ; 二
AND W10.02  ; 二
AND W10.03  ; 二
AND W10.04  ; 二
AND W10.05  ; 二
AND W10.06  ; 二
AND W10.07  ; 二
AND W10.08  ; 二
LD W11.09  ; 二
KEEP(011) W10.09  ; 二

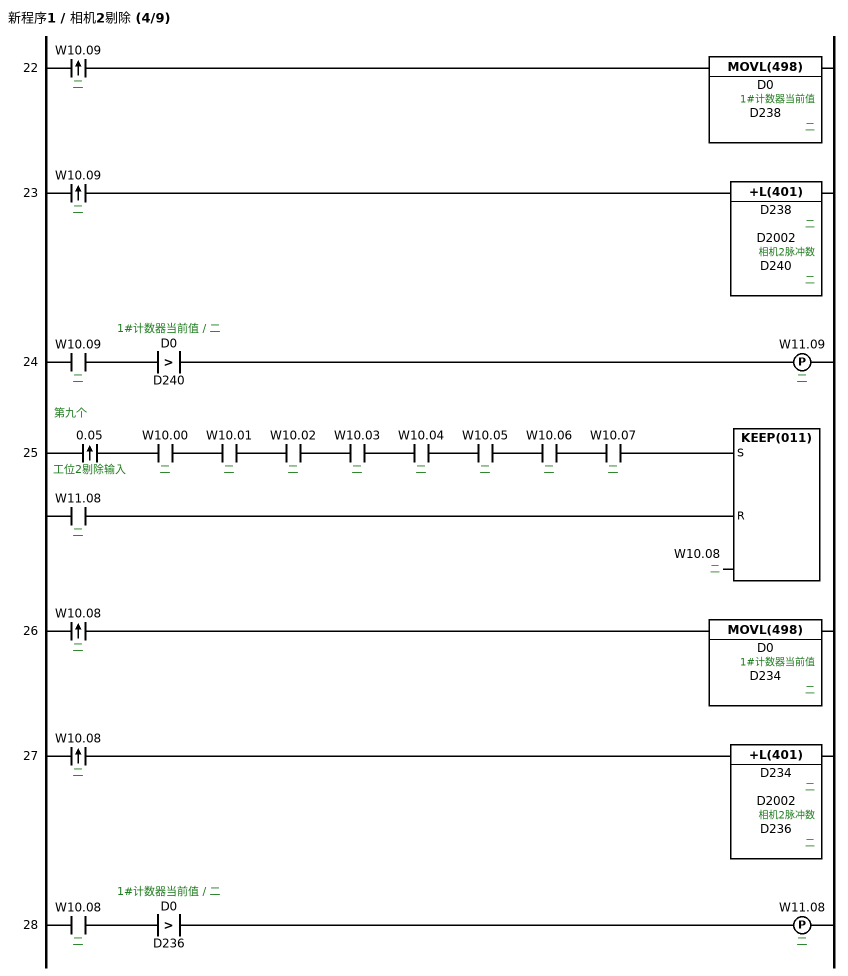
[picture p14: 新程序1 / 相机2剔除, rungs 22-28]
; rung 22
@LD W10.09  ; 二
MOVL(498) D0 D238  ; 1#计数器当前值, 二
; rung 23
@LD W10.09  ; 二
+L(401) D238 D2002 D240  ; 二, 相机2脉冲数
; rung 24
LD W10.09  ; 二
AND>L(321) D0 D240  ; 1#计数器当前值, 二
DIFU(013) W11.09  ; 二
; rung 25: 第九个
@LD 0.05  ; 工位2剔除输入
AND W10.00  ; 二
AND W10.01  ; 二
AND W10.02  ; 二
AND W10.03  ; 二
AND W10.04  ; 二
AND W10.05  ; 二
AND W10.06  ; 二
AND W10.07  ; 二
LD W11.08  ; 二
KEEP(011) W10.08  ; 二
; rung 26
@LD W10.08  ; 二
MOVL(498) D0 D234  ; 1#计数器当前值, 二
; rung 27
@LD W10.08  ; 二
+L(401) D234 D2002 D236  ; 二, 相机2脉冲数
; rung 28
LD W10.08  ; 二
AND>L(321) D0 D236  ; 1#计数器当前值, 二
DIFU(013) W11.08  ; 二

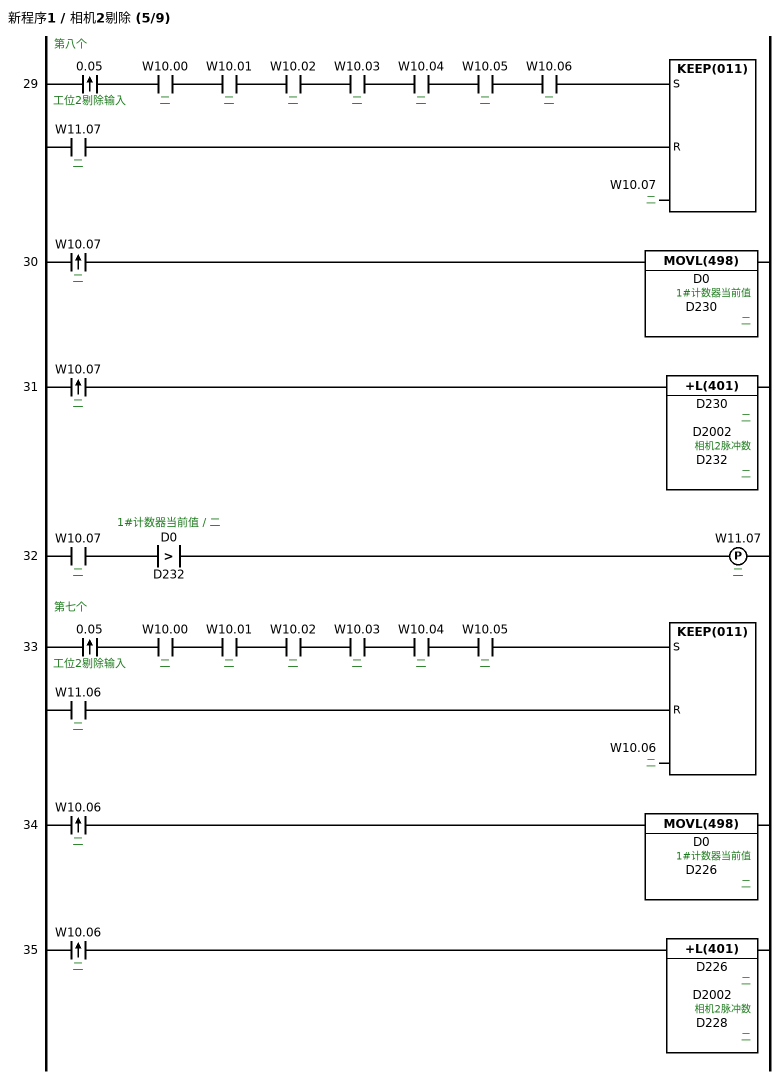
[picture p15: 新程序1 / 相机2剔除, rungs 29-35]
; rung 29: 第八个
@LD 0.05  ; 工位2剔除输入
AND W10.00  ; 二
AND W10.01  ; 二
AND W10.02  ; 二
AND W10.03  ; 二
AND W10.04  ; 二
AND W10.05  ; 二
AND W10.06  ; 二
LD W11.07  ; 二
KEEP(011) W10.07  ; 二
; rung 30
@LD W10.07  ; 二
MOVL(498) D0 D230  ; 1#计数器当前值, 二
; rung 31
@LD W10.07  ; 二
+L(401) D230 D2002 D232  ; 二, 相机2脉冲数
; rung 32
LD W10.07  ; 二
AND>L(321) D0 D232  ; 1#计数器当前值, 二
DIFU(013) W11.07  ; 二
; rung 33: 第七个
@LD 0.05  ; 工位2剔除输入
AND W10.00  ; 二
AND W10.01  ; 二
AND W10.02  ; 二
AND W10.03  ; 二
AND W10.04  ; 二
AND W10.05  ; 二
LD W11.06  ; 二
KEEP(011) W10.06  ; 二
; rung 34
@LD W10.06  ; 二
MOVL(498) D0 D226  ; 1#计数器当前值, 二
; rung 35
@LD W10.06  ; 二
+L(401) D226 D2002 D228  ; 二, 相机2脉冲数

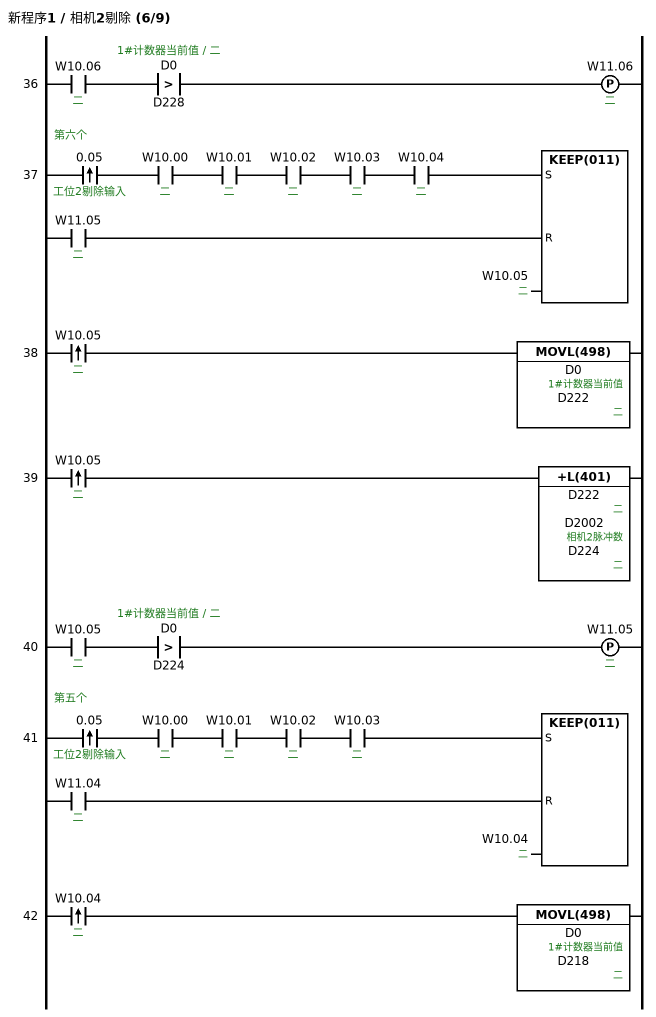
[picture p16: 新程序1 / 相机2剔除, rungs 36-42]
; rung 36
LD W10.06  ; 二
AND>L(321) D0 D228  ; 1#计数器当前值, 二
DIFU(013) W11.06  ; 二
; rung 37: 第六个
@LD 0.05  ; 工位2剔除输入
AND W10.00  ; 二
AND W10.01  ; 二
AND W10.02  ; 二
AND W10.03  ; 二
AND W10.04  ; 二
LD W11.05  ; 二
KEEP(011) W10.05  ; 二
; rung 38
@LD W10.05  ; 二
MOVL(498) D0 D222  ; 1#计数器当前值, 二
; rung 39
@LD W10.05  ; 二
+L(401) D222 D2002 D224  ; 二, 相机2脉冲数
; rung 40
LD W10.05  ; 二
AND>L(321) D0 D224  ; 1#计数器当前值, 二
DIFU(013) W11.05  ; 二
; rung 41: 第五个
@LD 0.05  ; 工位2剔除输入
AND W10.00  ; 二
AND W10.01  ; 二
AND W10.02  ; 二
AND W10.03  ; 二
LD W11.04  ; 二
KEEP(011) W10.04  ; 二
; rung 42
@LD W10.04  ; 二
MOVL(498) D0 D218  ; 1#计数器当前值, 二

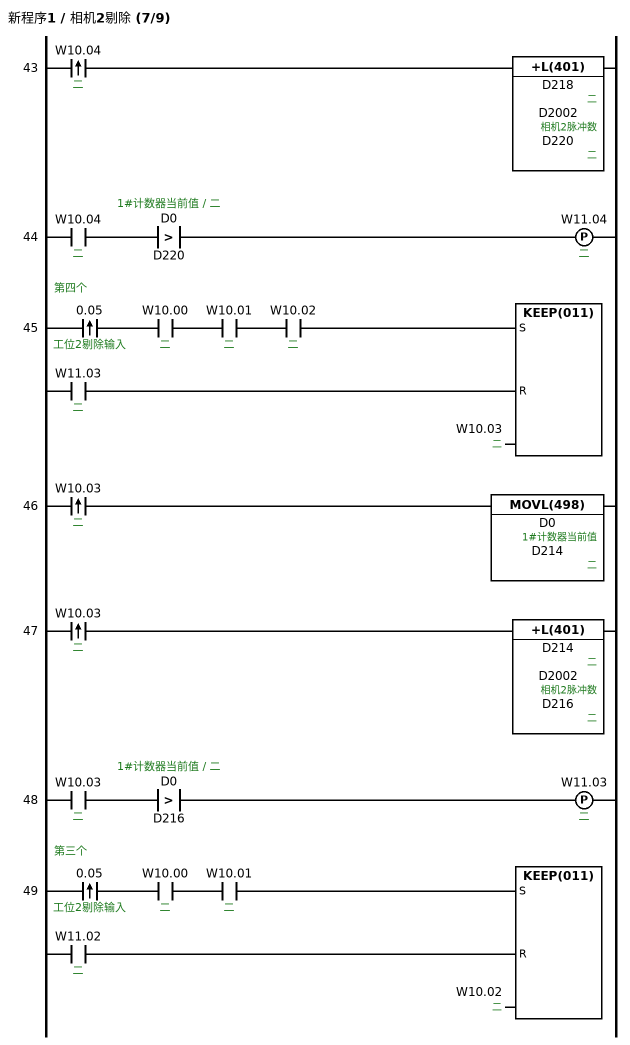
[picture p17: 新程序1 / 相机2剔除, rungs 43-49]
; rung 43
@LD W10.04  ; 二
+L(401) D218 D2002 D220  ; 二, 相机2脉冲数
; rung 44
LD W10.04  ; 二
AND>L(321) D0 D220  ; 1#计数器当前值, 二
DIFU(013) W11.04  ; 二
; rung 45: 第四个
@LD 0.05  ; 工位2剔除输入
AND W10.00  ; 二
AND W10.01  ; 二
AND W10.02  ; 二
LD W11.03  ; 二
KEEP(011) W10.03  ; 二
; rung 46
@LD W10.03  ; 二
MOVL(498) D0 D214  ; 1#计数器当前值, 二
; rung 47
@LD W10.03  ; 二
+L(401) D214 D2002 D216  ; 二, 相机2脉冲数
; rung 48
LD W10.03  ; 二
AND>L(321) D0 D216  ; 1#计数器当前值, 二
DIFU(013) W11.03  ; 二
; rung 49: 第三个
@LD 0.05  ; 工位2剔除输入
AND W10.00  ; 二
AND W10.01  ; 二
LD W11.02  ; 二
KEEP(011) W10.02  ; 二

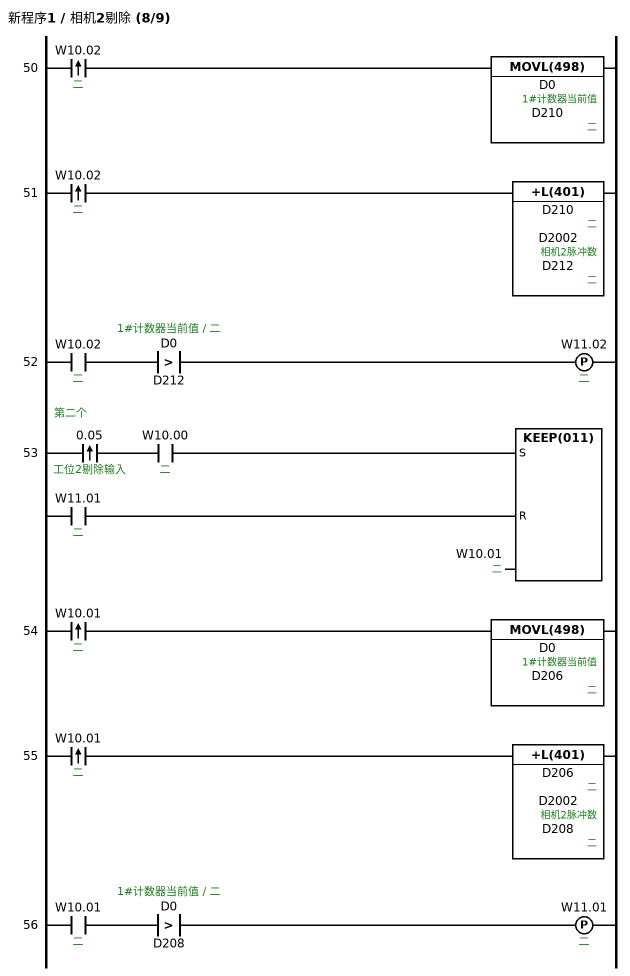
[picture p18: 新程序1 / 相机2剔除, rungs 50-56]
; rung 50
@LD W10.02  ; 二
MOVL(498) D0 D210  ; 1#计数器当前值, 二
; rung 51
@LD W10.02  ; 二
+L(401) D210 D2002 D212  ; 二, 相机2脉冲数
; rung 52
LD W10.02  ; 二
AND>L(321) D0 D212  ; 1#计数器当前值, 二
DIFU(013) W11.02  ; 二
; rung 53: 第二个
@LD 0.05  ; 工位2剔除输入
AND W10.00  ; 二
LD W11.01  ; 二
KEEP(011) W10.01  ; 二
; rung 54
@LD W10.01  ; 二
MOVL(498) D0 D206  ; 1#计数器当前值, 二
; rung 55
@LD W10.01  ; 二
+L(401) D206 D2002 D208  ; 二, 相机2脉冲数
; rung 56
LD W10.01  ; 二
AND>L(321) D0 D208  ; 1#计数器当前值, 二
DIFU(013) W11.01  ; 二

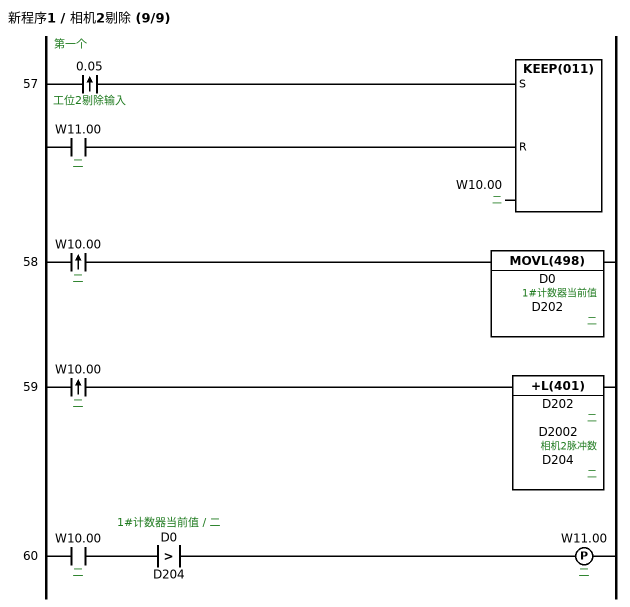
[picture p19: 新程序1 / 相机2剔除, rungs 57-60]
; rung 57: 第一个
@LD 0.05  ; 工位2剔除输入
LD W11.00  ; 二
KEEP(011) W10.00  ; 二
; rung 58
@LD W10.00  ; 二
MOVL(498) D0 D202  ; 1#计数器当前值, 二
; rung 59
@LD W10.00  ; 二
+L(401) D202 D2002 D204  ; 二, 相机2脉冲数
; rung 60
LD W10.00  ; 二
AND>L(321) D0 D204  ; 1#计数器当前值, 二
DIFU(013) W11.00  ; 二

### Section 相机3剔除

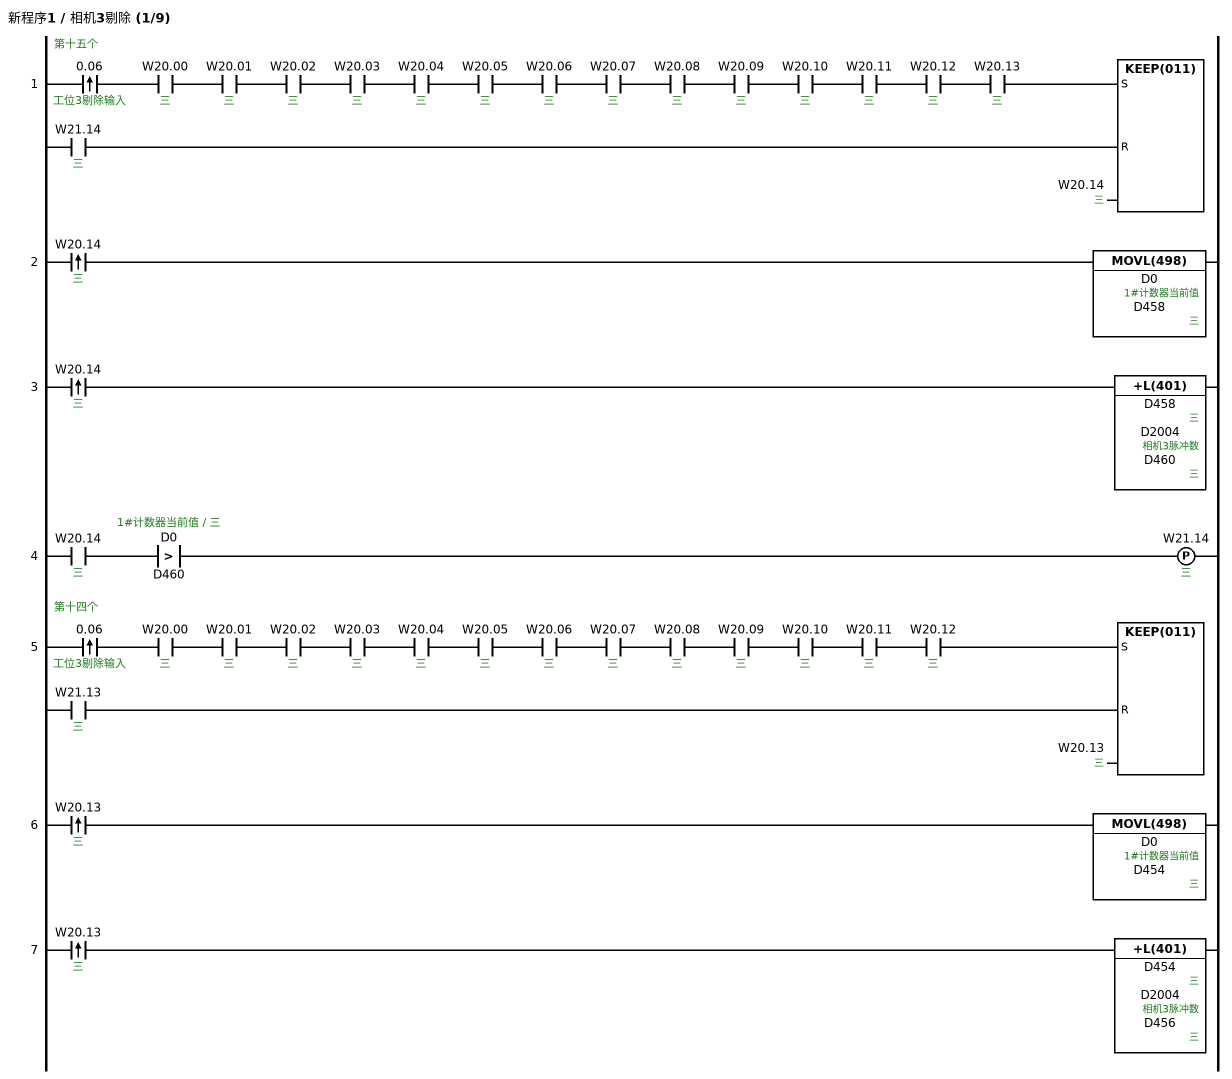
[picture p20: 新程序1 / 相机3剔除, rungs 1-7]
; rung 1: 第十五个
@LD 0.06  ; 工位3剔除输入
AND W20.00  ; 三
AND W20.01  ; 三
AND W20.02  ; 三
AND W20.03  ; 三
AND W20.04  ; 三
AND W20.05  ; 三
AND W20.06  ; 三
AND W20.07  ; 三
AND W20.08  ; 三
AND W20.09  ; 三
AND W20.10  ; 三
AND W20.11  ; 三
AND W20.12  ; 三
AND W20.13  ; 三
LD W21.14  ; 三
KEEP(011) W20.14  ; 三
; rung 2
@LD W20.14  ; 三
MOVL(498) D0 D458  ; 1#计数器当前值, 三
; rung 3
@LD W20.14  ; 三
+L(401) D458 D2004 D460  ; 三, 相机3脉冲数
; rung 4
LD W20.14  ; 三
AND>L(321) D0 D460  ; 1#计数器当前值, 三
DIFU(013) W21.14  ; 三
; rung 5: 第十四个
@LD 0.06  ; 工位3剔除输入
AND W20.00  ; 三
AND W20.01  ; 三
AND W20.02  ; 三
AND W20.03  ; 三
AND W20.04  ; 三
AND W20.05  ; 三
AND W20.06  ; 三
AND W20.07  ; 三
AND W20.08  ; 三
AND W20.09  ; 三
AND W20.10  ; 三
AND W20.11  ; 三
AND W20.12  ; 三
LD W21.13  ; 三
KEEP(011) W20.13  ; 三
; rung 6
@LD W20.13  ; 三
MOVL(498) D0 D454  ; 1#计数器当前值, 三
; rung 7
@LD W20.13  ; 三
+L(401) D454 D2004 D456  ; 三, 相机3脉冲数

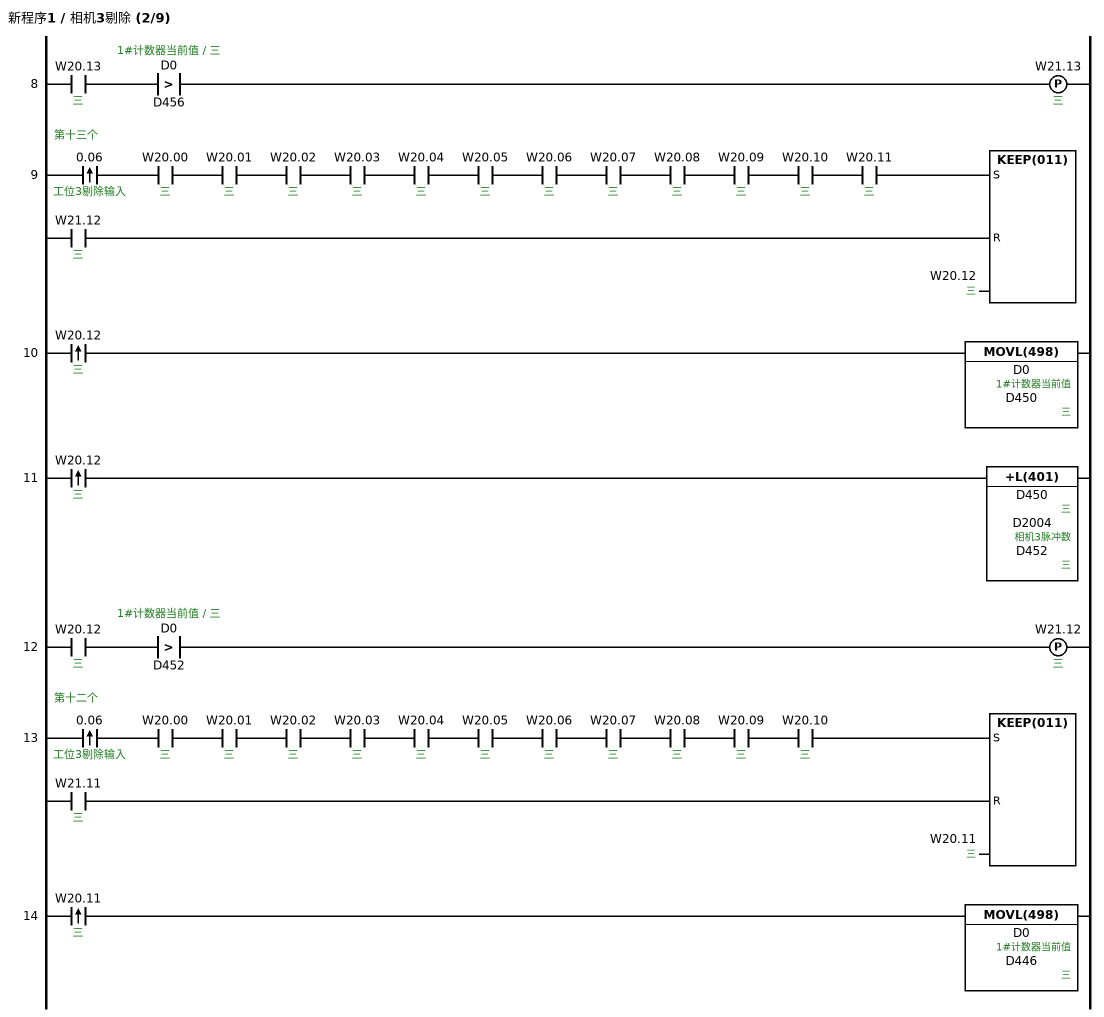
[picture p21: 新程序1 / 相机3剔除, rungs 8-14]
; rung 8
LD W20.13  ; 三
AND>L(321) D0 D456  ; 1#计数器当前值, 三
DIFU(013) W21.13  ; 三
; rung 9: 第十三个
@LD 0.06  ; 工位3剔除输入
AND W20.00  ; 三
AND W20.01  ; 三
AND W20.02  ; 三
AND W20.03  ; 三
AND W20.04  ; 三
AND W20.05  ; 三
AND W20.06  ; 三
AND W20.07  ; 三
AND W20.08  ; 三
AND W20.09  ; 三
AND W20.10  ; 三
AND W20.11  ; 三
LD W21.12  ; 三
KEEP(011) W20.12  ; 三
; rung 10
@LD W20.12  ; 三
MOVL(498) D0 D450  ; 1#计数器当前值, 三
; rung 11
@LD W20.12  ; 三
+L(401) D450 D2004 D452  ; 三, 相机3脉冲数
; rung 12
LD W20.12  ; 三
AND>L(321) D0 D452  ; 1#计数器当前值, 三
DIFU(013) W21.12  ; 三
; rung 13: 第十二个
@LD 0.06  ; 工位3剔除输入
AND W20.00  ; 三
AND W20.01  ; 三
AND W20.02  ; 三
AND W20.03  ; 三
AND W20.04  ; 三
AND W20.05  ; 三
AND W20.06  ; 三
AND W20.07  ; 三
AND W20.08  ; 三
AND W20.09  ; 三
AND W20.10  ; 三
LD W21.11  ; 三
KEEP(011) W20.11  ; 三
; rung 14
@LD W20.11  ; 三
MOVL(498) D0 D446  ; 1#计数器当前值, 三

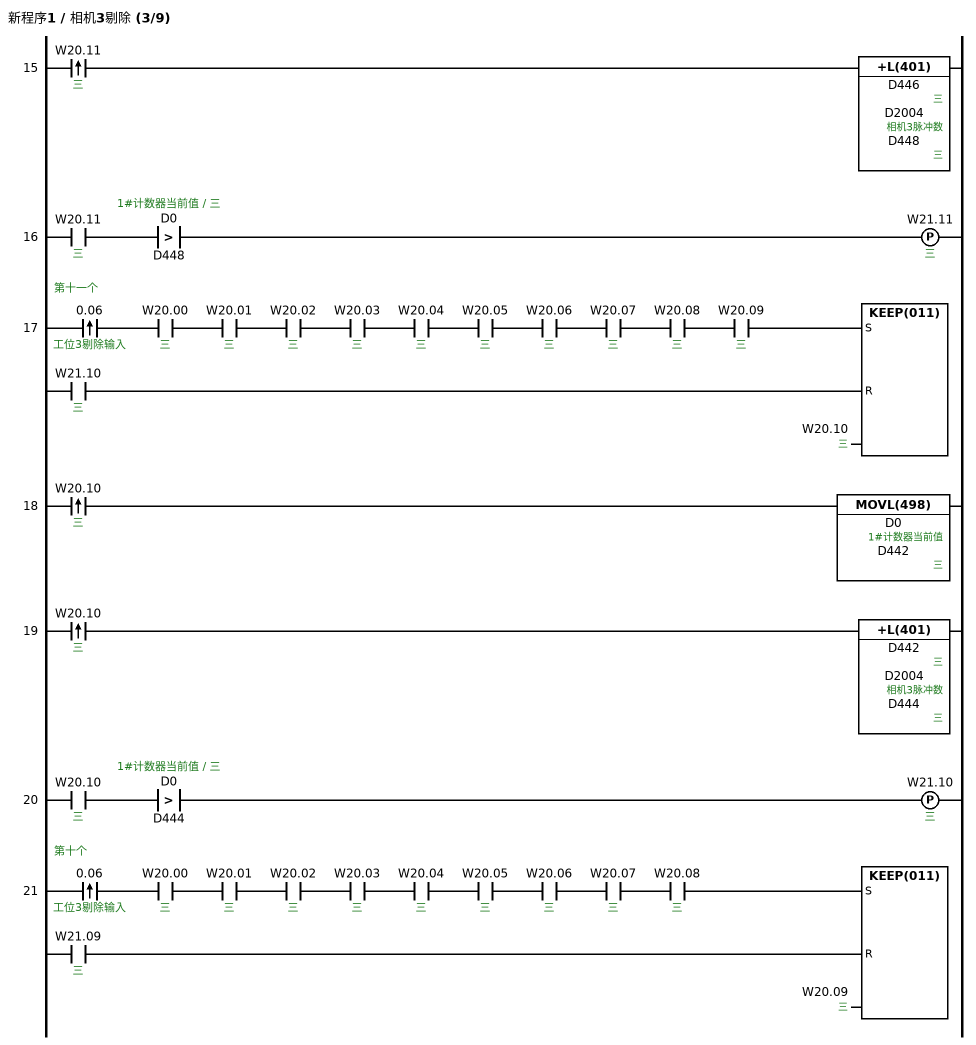
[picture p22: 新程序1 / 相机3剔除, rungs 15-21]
; rung 15
@LD W20.11  ; 三
+L(401) D446 D2004 D448  ; 三, 相机3脉冲数
; rung 16
LD W20.11  ; 三
AND>L(321) D0 D448  ; 1#计数器当前值, 三
DIFU(013) W21.11  ; 三
; rung 17: 第十一个
@LD 0.06  ; 工位3剔除输入
AND W20.00  ; 三
AND W20.01  ; 三
AND W20.02  ; 三
AND W20.03  ; 三
AND W20.04  ; 三
AND W20.05  ; 三
AND W20.06  ; 三
AND W20.07  ; 三
AND W20.08  ; 三
AND W20.09  ; 三
LD W21.10  ; 三
KEEP(011) W20.10  ; 三
; rung 18
@LD W20.10  ; 三
MOVL(498) D0 D442  ; 1#计数器当前值, 三
; rung 19
@LD W20.10  ; 三
+L(401) D442 D2004 D444  ; 三, 相机3脉冲数
; rung 20
LD W20.10  ; 三
AND>L(321) D0 D444  ; 1#计数器当前值, 三
DIFU(013) W21.10  ; 三
; rung 21: 第十个
@LD 0.06  ; 工位3剔除输入
AND W20.00  ; 三
AND W20.01  ; 三
AND W20.02  ; 三
AND W20.03  ; 三
AND W20.04  ; 三
AND W20.05  ; 三
AND W20.06  ; 三
AND W20.07  ; 三
AND W20.08  ; 三
LD W21.09  ; 三
KEEP(011) W20.09  ; 三

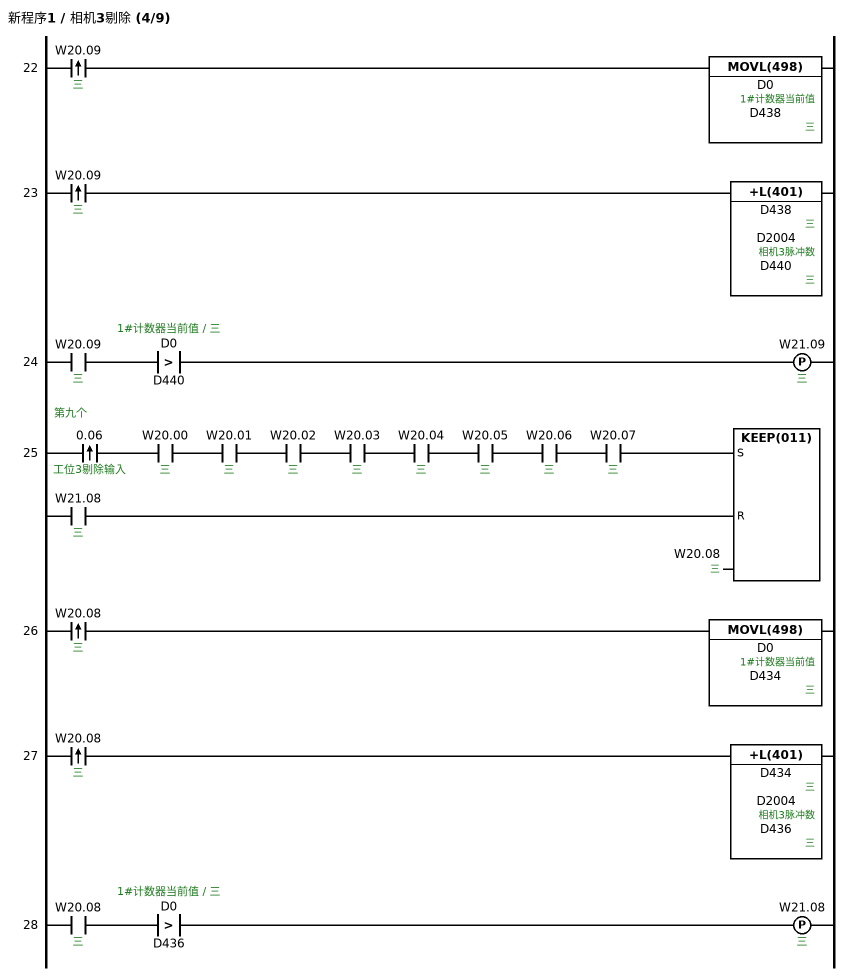
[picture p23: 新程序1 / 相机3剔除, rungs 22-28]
; rung 22
@LD W20.09  ; 三
MOVL(498) D0 D438  ; 1#计数器当前值, 三
; rung 23
@LD W20.09  ; 三
+L(401) D438 D2004 D440  ; 三, 相机3脉冲数
; rung 24
LD W20.09  ; 三
AND>L(321) D0 D440  ; 1#计数器当前值, 三
DIFU(013) W21.09  ; 三
; rung 25: 第九个
@LD 0.06  ; 工位3剔除输入
AND W20.00  ; 三
AND W20.01  ; 三
AND W20.02  ; 三
AND W20.03  ; 三
AND W20.04  ; 三
AND W20.05  ; 三
AND W20.06  ; 三
AND W20.07  ; 三
LD W21.08  ; 三
KEEP(011) W20.08  ; 三
; rung 26
@LD W20.08  ; 三
MOVL(498) D0 D434  ; 1#计数器当前值, 三
; rung 27
@LD W20.08  ; 三
+L(401) D434 D2004 D436  ; 三, 相机3脉冲数
; rung 28
LD W20.08  ; 三
AND>L(321) D0 D436  ; 1#计数器当前值, 三
DIFU(013) W21.08  ; 三

; rung 29: 第八个
@LD 0.06  ; 工位3剔除输入
AND W20.00  ; 三
AND W20.01  ; 三
AND W20.02  ; 三
AND W20.03  ; 三
AND W20.04  ; 三
AND W20.05  ; 三
AND W20.06  ; 三
LD W21.07  ; 三
KEEP(011) W20.07  ; 三
; rung 30
@LD W20.07  ; 三
MOVL(498) D0 D430  ; 1#计数器当前值, 三
; rung 31
@LD W20.07  ; 三
+L(401) D430 D2004 D432  ; 三, 相机3脉冲数
; rung 32
LD W20.07  ; 三
AND>L(321) D0 D432  ; 1#计数器当前值, 三
DIFU(013) W21.07  ; 三
; rung 33: 第七个
@LD 0.06  ; 工位3剔除输入
AND W20.00  ; 三
AND W20.01  ; 三
AND W20.02  ; 三
AND W20.03  ; 三
AND W20.04  ; 三
AND W20.05  ; 三
LD W21.06  ; 三
KEEP(011) W20.06  ; 三
; rung 34
@LD W20.06  ; 三
MOVL(498) D0 D426  ; 1#计数器当前值, 三
; rung 35
@LD W20.06  ; 三
+L(401) D426 D2004 D428  ; 三, 相机3脉冲数

; rung 36
LD W20.06  ; 三
AND>L(321) D0 D428  ; 1#计数器当前值, 三
DIFU(013) W21.06  ; 三
; rung 37: 第六个
@LD 0.06  ; 工位3剔除输入
AND W20.00  ; 三
AND W20.01  ; 三
AND W20.02  ; 三
AND W20.03  ; 三
AND W20.04  ; 三
LD W21.05  ; 三
KEEP(011) W20.05  ; 三
; rung 38
@LD W20.05  ; 三
MOVL(498) D0 D422  ; 1#计数器当前值, 三
; rung 39
@LD W20.05  ; 三
+L(401) D422 D2004 D424  ; 三, 相机3脉冲数
; rung 40
LD W20.05  ; 三
AND>L(321) D0 D424  ; 1#计数器当前值, 三
DIFU(013) W21.05  ; 三
; rung 41: 第五个
@LD 0.06  ; 工位3剔除输入
AND W20.00  ; 三
AND W20.01  ; 三
AND W20.02  ; 三
AND W20.03  ; 三
LD W21.04  ; 三
KEEP(011) W20.04  ; 三
; rung 42
@LD W20.04  ; 三
MOVL(498) D0 D418  ; 1#计数器当前值, 三

; rung 43
@LD W20.04  ; 三
+L(401) D418 D2004 D420  ; 三, 相机3脉冲数
; rung 44
LD W20.04  ; 三
AND>L(321) D0 D420  ; 1#计数器当前值, 三
DIFU(013) W21.04  ; 三
; rung 45: 第四个
@LD 0.06  ; 工位3剔除输入
AND W20.00  ; 三
AND W20.01  ; 三
AND W20.02  ; 三
LD W21.03  ; 三
KEEP(011) W20.03  ; 三
; rung 46
@LD W20.03  ; 三
MOVL(498) D0 D414  ; 1#计数器当前值, 三
; rung 47
@LD W20.03  ; 三
+L(401) D414 D2004 D416  ; 三, 相机3脉冲数
; rung 48
LD W20.03  ; 三
AND>L(321) D0 D416  ; 1#计数器当前值, 三
DIFU(013) W21.03  ; 三
; rung 49: 第三个
@LD 0.06  ; 工位3剔除输入
AND W20.00  ; 三
AND W20.01  ; 三
LD W21.02  ; 三
KEEP(011) W20.02  ; 三

; rung 50
@LD W20.02  ; 三
MOVL(498) D0 D410  ; 1#计数器当前值, 三
; rung 51
@LD W20.02  ; 三
+L(401) D410 D2004 D412  ; 三, 相机3脉冲数
; rung 52
LD W20.02  ; 三
AND>L(321) D0 D412  ; 1#计数器当前值, 三
DIFU(013) W21.02  ; 三
; rung 53: 第二个
@LD 0.06  ; 工位3剔除输入
AND W20.00  ; 三
LD W21.01  ; 三
KEEP(011) W20.01  ; 三
; rung 54
@LD W20.01  ; 三
MOVL(498) D0 D406  ; 1#计数器当前值, 三
; rung 55
@LD W20.01  ; 三
+L(401) D406 D2004 D408  ; 三, 相机3脉冲数
; rung 56
LD W20.01  ; 三
AND>L(321) D0 D408  ; 1#计数器当前值, 三
DIFU(013) W21.01  ; 三

; rung 57: 第一个
@LD 0.06  ; 工位3剔除输入
LD W21.00  ; 三
KEEP(011) W20.00  ; 三
; rung 58
@LD W20.00  ; 三
MOVL(498) D0 D402  ; 1#计数器当前值, 三
; rung 59
@LD W20.00  ; 三
+L(401) D402 D2004 D404  ; 三, 相机3脉冲数
; rung 60
LD W20.00  ; 三
AND>L(321) D0 D404  ; 1#计数器当前值, 三
DIFU(013) W21.00  ; 三

### Section 相机4剔除

; rung 1: 第十五个
@LD 0.08
AND W30.00  ; 四五
AND W30.01  ; 四五
AND W30.02  ; 四五
AND W30.03  ; 四五
AND W30.04  ; 四五
AND W30.05  ; 四五
AND W30.06  ; 四五
AND W30.07  ; 四五
AND W30.08  ; 四五
AND W30.09  ; 四五
AND W30.10  ; 四五
AND W30.11  ; 四五
AND W30.12  ; 四五
AND W30.13  ; 四五
LD W31.14  ; 四五
KEEP(011) W30.14  ; 四五
; rung 2
@LD W30.14  ; 四五
MOVL(498) D0 D658  ; 1#计数器当前值, 四
; rung 3
@LD W30.14  ; 四五
+L(401) D658 D2006 D660  ; 四, 相机4脉冲数
; rung 4
LD W30.14  ; 四五
AND>L(321) D0 D660  ; 1#计数器当前值, 四
DIFU(013) W31.14  ; 四五
; rung 5: 第十四个
@LD 0.08
AND W30.00  ; 四五
AND W30.01  ; 四五
AND W30.02  ; 四五
AND W30.03  ; 四五
AND W30.04  ; 四五
AND W30.05  ; 四五
AND W30.06  ; 四五
AND W30.07  ; 四五
AND W30.08  ; 四五
AND W30.09  ; 四五
AND W30.10  ; 四五
AND W30.11  ; 四五
AND W30.12  ; 四五
LD W31.13  ; 四五
KEEP(011) W30.13  ; 四五
; rung 6
@LD W30.13  ; 四五
MOVL(498) D0 D654  ; 1#计数器当前值, 四
; rung 7
@LD W30.13  ; 四五
+L(401) D654 D2006 D656  ; 四, 相机4脉冲数

; rung 8
LD W30.13  ; 四五
AND>L(321) D0 D656  ; 1#计数器当前值, 四
DIFU(013) W31.13  ; 四五
; rung 9: 第十三个
@LD 0.08
AND W30.00  ; 四五
AND W30.01  ; 四五
AND W30.02  ; 四五
AND W30.03  ; 四五
AND W30.04  ; 四五
AND W30.05  ; 四五
AND W30.06  ; 四五
AND W30.07  ; 四五
AND W30.08  ; 四五
AND W30.09  ; 四五
AND W30.10  ; 四五
AND W30.11  ; 四五
LD W31.12  ; 四五
KEEP(011) W30.12  ; 四五
; rung 10
@LD W30.12  ; 四五
MOVL(498) D0 D650  ; 1#计数器当前值, 四
; rung 11
@LD W30.12  ; 四五
+L(401) D650 D2006 D652  ; 四, 相机4脉冲数
; rung 12
LD W30.12  ; 四五
AND>L(321) D0 D652  ; 1#计数器当前值, 四
DIFU(013) W31.12  ; 四五
; rung 13: 第十二个
@LD 0.08
AND W30.00  ; 四五
AND W30.01  ; 四五
AND W30.02  ; 四五
AND W30.03  ; 四五
AND W30.04  ; 四五
AND W30.05  ; 四五
AND W30.06  ; 四五
AND W30.07  ; 四五
AND W30.08  ; 四五
AND W30.09  ; 四五
AND W30.10  ; 四五
LD W31.11  ; 四五
KEEP(011) W30.11  ; 四五
; rung 14
@LD W30.11  ; 四五
MOVL(498) D0 D646  ; 1#计数器当前值, 四

; rung 15
@LD W30.11  ; 四五
+L(401) D646 D2006 D648  ; 四, 相机4脉冲数
; rung 16
LD W30.11  ; 四五
AND>L(321) D0 D648  ; 1#计数器当前值, 四
DIFU(013) W31.11  ; 四五
; rung 17: 第十一个
@LD 0.08
AND W30.00  ; 四五
AND W30.01  ; 四五
AND W30.02  ; 四五
AND W30.03  ; 四五
AND W30.04  ; 四五
AND W30.05  ; 四五
AND W30.06  ; 四五
AND W30.07  ; 四五
AND W30.08  ; 四五
AND W30.09  ; 四五
LD W31.10  ; 四五
KEEP(011) W30.10  ; 四五
; rung 18
@LD W30.10  ; 四五
MOVL(498) D0 D642  ; 1#计数器当前值, 四
; rung 19
@LD W30.10  ; 四五
+L(401) D642 D2006 D644  ; 四, 相机4脉冲数
; rung 20
LD W30.10  ; 四五
AND>L(321) D0 D644  ; 1#计数器当前值, 四
DIFU(013) W31.10  ; 四五
; rung 21: 第十个
@LD 0.08
AND W30.00  ; 四五
AND W30.01  ; 四五
AND W30.02  ; 四五
AND W30.03  ; 四五
AND W30.04  ; 四五
AND W30.05  ; 四五
AND W30.06  ; 四五
AND W30.07  ; 四五
AND W30.08  ; 四五
LD W31.09  ; 四五
KEEP(011) W30.09  ; 四五

; rung 22
@LD W30.09  ; 四五
MOVL(498) D0 D638  ; 1#计数器当前值, 四
; rung 23
@LD W30.09  ; 四五
+L(401) D638 D2006 D640  ; 四, 相机4脉冲数
; rung 24
LD W30.09  ; 四五
AND>L(321) D0 D640  ; 1#计数器当前值, 四
DIFU(013) W31.09  ; 四五
; rung 25: 第九个
@LD 0.08
AND W30.00  ; 四五
AND W30.01  ; 四五
AND W30.02  ; 四五
AND W30.03  ; 四五
AND W30.04  ; 四五
AND W30.05  ; 四五
AND W30.06  ; 四五
AND W30.07  ; 四五
LD W21.08  ; 三
KEEP(011) W30.08  ; 四五
; rung 26
@LD W30.08  ; 四五
MOVL(498) D0 D634  ; 1#计数器当前值, 四
; rung 27
@LD W30.08  ; 四五
+L(401) D634 D2006 D636  ; 四, 相机4脉冲数
; rung 28
LD W30.08  ; 四五
AND>L(321) D0 D636  ; 1#计数器当前值, 四
DIFU(013) W31.08  ; 四五

; rung 29: 第八个
@LD 0.08
AND W30.00  ; 四五
AND W30.01  ; 四五
AND W30.02  ; 四五
AND W30.03  ; 四五
AND W30.04  ; 四五
AND W30.05  ; 四五
AND W30.06  ; 四五
LD W31.07  ; 四五
KEEP(011) W30.07  ; 四五
; rung 30
@LD W30.07  ; 四五
MOVL(498) D0 D630  ; 1#计数器当前值, 四
; rung 31
@LD W30.07  ; 四五
+L(401) D630 D2006 D632  ; 四, 相机4脉冲数
; rung 32
LD W30.07  ; 四五
AND>L(321) D0 D632  ; 1#计数器当前值, 四
DIFU(013) W31.07  ; 四五
; rung 33: 第七个
@LD 0.08
AND W30.00  ; 四五
AND W30.01  ; 四五
AND W30.02  ; 四五
AND W30.03  ; 四五
AND W30.04  ; 四五
AND W30.05  ; 四五
LD W31.06  ; 四五
KEEP(011) W30.06  ; 四五
; rung 34
@LD W30.06  ; 四五
MOVL(498) D0 D626  ; 1#计数器当前值, 四
; rung 35
@LD W30.06  ; 四五
+L(401) D626 D2006 D628  ; 四, 相机4脉冲数

; rung 36
LD W30.06  ; 四五
AND>L(321) D0 D628  ; 1#计数器当前值, 四
DIFU(013) W31.06  ; 四五
; rung 37: 第六个
@LD 0.08
AND W30.00  ; 四五
AND W30.01  ; 四五
AND W30.02  ; 四五
AND W30.03  ; 四五
AND W30.04  ; 四五
LD W31.05  ; 四五
KEEP(011) W30.05  ; 四五
; rung 38
@LD W30.05  ; 四五
MOVL(498) D0 D622  ; 1#计数器当前值, 四
; rung 39
@LD W30.05  ; 四五
+L(401) D622 D2006 D624  ; 四, 相机4脉冲数
; rung 40
LD W30.05  ; 四五
AND>L(321) D0 D624  ; 1#计数器当前值, 四
DIFU(013) W31.05  ; 四五
; rung 41: 第五个
@LD 0.08
AND W30.00  ; 四五
AND W30.01  ; 四五
AND W30.02  ; 四五
AND W30.03  ; 四五
LD W31.04  ; 四五
KEEP(011) W30.04  ; 四五
; rung 42
@LD W30.04  ; 四五
MOVL(498) D0 D618  ; 1#计数器当前值, 四

; rung 43
@LD W30.04  ; 四五
+L(401) D618 D2006 D620  ; 四, 相机4脉冲数
; rung 44
LD W30.04  ; 四五
AND>L(321) D0 D620  ; 1#计数器当前值, 四
DIFU(013) W31.04  ; 四五
; rung 45: 第四个
@LD 0.08
AND W30.00  ; 四五
AND W30.01  ; 四五
AND W30.02  ; 四五
LD W31.03  ; 四五
KEEP(011) W30.03  ; 四五
; rung 46
@LD W30.03  ; 四五
MOVL(498) D0 D614  ; 1#计数器当前值, 四
; rung 47
@LD W30.03  ; 四五
+L(401) D614 D2006 D616  ; 四, 相机4脉冲数
; rung 48
LD W30.03  ; 四五
AND>L(321) D0 D616  ; 1#计数器当前值, 四
DIFU(013) W31.03  ; 四五
; rung 49: 第三个
@LD 0.08
AND W30.00  ; 四五
AND W30.01  ; 四五
LD W31.02  ; 四五
KEEP(011) W30.02  ; 四五

; rung 50
@LD W30.02  ; 四五
MOVL(498) D0 D610  ; 1#计数器当前值, 四
; rung 51
@LD W30.02  ; 四五
+L(401) D610 D2006 D612  ; 四, 相机4脉冲数
; rung 52
LD W30.02  ; 四五
AND>L(321) D0 D612  ; 1#计数器当前值, 四
DIFU(013) W31.02  ; 四五
; rung 53: 第二个
@LD 0.08
AND W30.00  ; 四五
LD W31.01  ; 四五
KEEP(011) W30.01  ; 四五
; rung 54
@LD W30.01  ; 四五
MOVL(498) D0 D606  ; 1#计数器当前值, 四
; rung 55
@LD W30.01  ; 四五
+L(401) D606 D2006 D608  ; 四, 相机4脉冲数
; rung 56
LD W30.01  ; 四五
AND>L(321) D0 D608  ; 1#计数器当前值, 四
DIFU(013) W31.01  ; 四五

; rung 57: 第一个
@LD 0.08
LD W31.00  ; 四五
KEEP(011) W30.00  ; 四五
; rung 58
@LD W30.00  ; 四五
MOVL(498) D0 D602  ; 1#计数器当前值, 四
; rung 59
@LD W30.00  ; 四五
+L(401) D602 D2006 D604  ; 四, 相机4脉冲数
; rung 60
LD W30.00  ; 四五
AND>L(321) D0 D604  ; 1#计数器当前值, 四
DIFU(013) W31.00  ; 四五

### Section 剔除输出

; rung 1: 相机1输出
LD W1.00  ; 一
OR W1.01  ; 一
OR W1.02  ; 一
OR W1.03  ; 一
OR W1.04  ; 一
OR W1.05  ; 一
OR W1.06  ; 一
OR W1.07  ; 一
OR W1.08  ; 一
OR W1.09  ; 一
OR W1.10  ; 一
OR W1.11  ; 一
OR W1.12  ; 一
OR W1.13  ; 一
OR W1.14  ; 一
LD T000
KEEP(011) W50.00
; rung 2
LD W50.00
TMHHX(552) 000 D2008  ; 吹气时间

; rung 3: 相机2输出
LD W11.00  ; 二
OR W11.01  ; 二
OR W11.02  ; 二
OR W11.03  ; 二
OR W11.04  ; 二
OR W11.05  ; 二
OR W11.06  ; 二
OR W11.07  ; 二
OR W11.08  ; 二
OR W11.09  ; 二
OR W11.10  ; 二
OR W11.11  ; 二
OR W11.12  ; 二
OR W11.13  ; 二
OR W11.14  ; 二
LD T001
KEEP(011) W50.01
; rung 4
LD W50.01
TMHHX(552) 001 D2008  ; 吹气时间

; rung 5: 相机3输出
LD W21.00  ; 三
OR W21.01  ; 三
OR W21.02  ; 三
OR W21.03  ; 三
OR W21.04  ; 三
OR W21.05  ; 三
OR W21.06  ; 三
OR W21.07  ; 三
OR W21.08  ; 三
OR W21.09  ; 三
OR W21.10  ; 三
OR W21.11  ; 三
OR W21.12  ; 三
OR W21.13  ; 三
OR W21.14  ; 三
LD T002
KEEP(011) W50.02
; rung 6
LD W50.02
TMHHX(552) 002 D2008  ; 吹气时间

; rung 7: 相机45输出
LD W31.00  ; 四五
OR W31.01  ; 四五
OR W31.02  ; 四五
OR W31.03  ; 四五
OR W31.04  ; 四五
OR W31.05  ; 四五
OR W31.06  ; 四五
OR W31.07  ; 四五
OR W31.08  ; 四五
OR W31.09  ; 四五
OR W31.10  ; 四五
OR W31.11  ; 四五
OR W31.12  ; 四五
OR W31.13  ; 四五
OR W31.14  ; 四五
LD T003
KEEP(011) W50.03
; rung 8
LD W50.03
TMHHX(552) 003 D2008  ; 吹气时间

; rung 9
LD W50.00
OR W50.01
OR W50.02
OR W50.03
OUT 100.00  ; 剔除输出
; rung 11
LD>L(321) D0 &100000  ; 1#计数器当前值
ANDNOT W0.00  ; 一
ANDNOT W0.01  ; 一
ANDNOT W0.02  ; 一
ANDNOT W0.03  ; 一
ANDNOT W0.04  ; 一
ANDNOT W0.05  ; 一
ANDNOT W0.06  ; 一
ANDNOT W0.07  ; 一
ANDNOT W0.08  ; 一
ANDNOT W0.09  ; 一
ANDNOT W0.10  ; 一
ANDNOT W0.11  ; 一
ANDNOT W0.12  ; 一
ANDNOT W0.13  ; 一
ANDNOT W0.14  ; 一
OUT W5.00
; rung 12
LD>L(321) D0 &100000  ; 1#计数器当前值
OUT TR0
ANDNOT W10.00  ; 二
ANDNOT W10.01  ; 二
ANDNOT W10.02  ; 二
ANDNOT W10.03  ; 二
ANDNOT W10.04  ; 二
ANDNOT W10.05  ; 二
ANDNOT W10.06  ; 二
ANDNOT W10.07  ; 二
ANDNOT W10.08  ; 二
ANDNOT W10.09  ; 二
ANDNOT W10.10  ; 二
ANDNOT W10.11  ; 二
ANDNOT W10.12  ; 二
ANDNOT W10.13  ; 二
ANDNOT W10.14  ; 二
OUT W5.01
LD TR0
ANDNOT W20.00  ; 三
ANDNOT W20.01  ; 三
ANDNOT W20.02  ; 三
ANDNOT W20.03  ; 三
ANDNOT W20.04  ; 三
ANDNOT W20.05  ; 三
ANDNOT W20.06  ; 三
ANDNOT W20.07  ; 三
ANDNOT W20.08  ; 三
ANDNOT W20.09  ; 三
ANDNOT W20.10  ; 三
ANDNOT W20.11  ; 三
ANDNOT W20.12  ; 三
ANDNOT W20.13  ; 三
ANDNOT W20.14  ; 三
OUT W5.02
LD TR0
ANDNOT W30.00  ; 四五
ANDNOT W30.01  ; 四五
ANDNOT W30.02  ; 四五
ANDNOT W30.03  ; 四五
ANDNOT W30.04  ; 四五
ANDNOT W30.05  ; 四五
ANDNOT W30.06  ; 四五
ANDNOT W30.07  ; 四五
ANDNOT W30.08  ; 四五
ANDNOT W30.09  ; 四五
ANDNOT W30.10  ; 四五
ANDNOT W30.11  ; 四五
ANDNOT W30.12  ; 四五
ANDNOT W30.13  ; 四五
ANDNOT W30.14  ; 四五
OUT W5.03
; rung 14
LD W5.00
AND W5.01
AND W5.02
AND W5.03
OUT A531.00

### Section 喷码剔除

; rung 0: 第四个
@LD 0.07  ; 喷码剔除输入
AND W80.00
AND W80.01
AND W80.02
LD T014
KEEP(011) W80.03
; rung 1
LD W80.03
TMHHX(552) 014 D6000  ; 喷码延时时间
; rung 2
LD T014
DIFU(013) W81.03
; rung 3: 第三个
@LD 0.07  ; 喷码剔除输入
AND W80.00
AND W80.01
LD T013
KEEP(011) W80.02
; rung 4
LD W80.02
TMHHX(552) 013 D6000  ; 喷码延时时间
; rung 5
LD T013
DIFU(013) W81.02
; rung 6: 第二个
@LD 0.07  ; 喷码剔除输入
AND W80.00
LD T012
KEEP(011) W80.01
; rung 7
LD W80.01
TMHHX(552) 012 D6000  ; 喷码延时时间

; rung 8
LD T012
DIFU(013) W81.01
; rung 9: 第一个
@LD 0.07  ; 喷码剔除输入
LD T011
KEEP(011) W80.00
; rung 10
LD W80.00
TMHHX(552) 011 D6000  ; 喷码延时时间
; rung 11
LD T011
DIFU(013) W81.00
; rung 12: 输出
LD W81.00
OR W81.01
OR W81.02
OR W81.03
LD T015
KEEP(011) 100.01  ; 剔除
; rung 13
LD 100.01  ; 剔除
TMHHX(552) 015 &50

### Section END
; rung 0
END(001)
